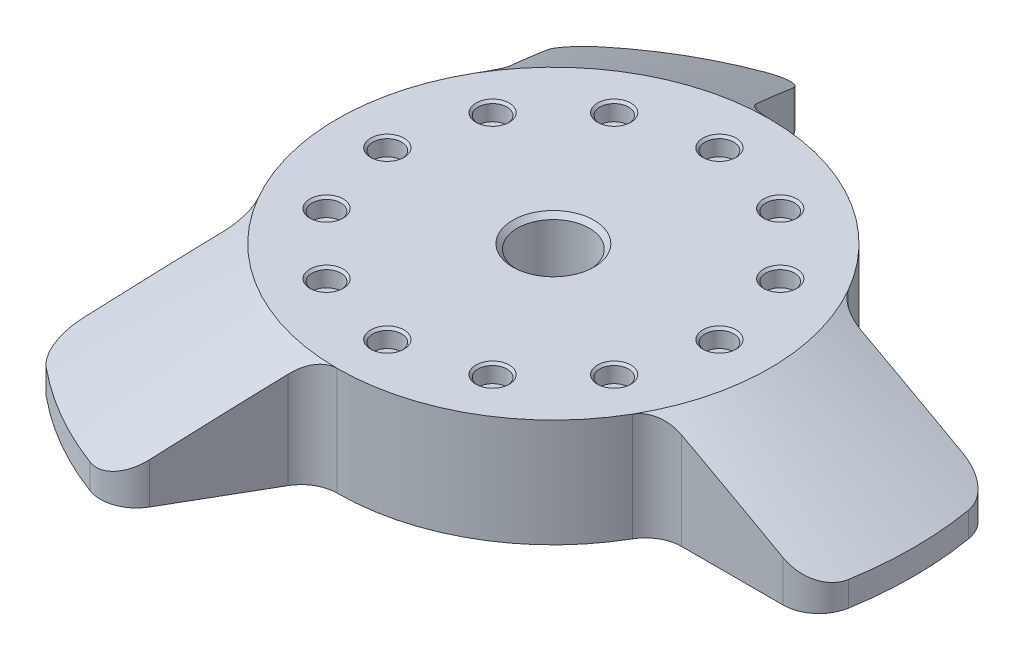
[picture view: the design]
ISO-10303-21;
HEADER;
FILE_DESCRIPTION(('STEP AP214'),'2;1');
FILE_NAME('part.step','',(''),(''),'','','');
FILE_SCHEMA(('AUTOMOTIVE_DESIGN { 1 0 10303 214 1 1 1 1 }'));
ENDSEC;
DATA;
#1=APPLICATION_CONTEXT('core data for automotive mechanical design processes');
#2=APPLICATION_PROTOCOL_DEFINITION('international standard','automotive_design',2000,#1);
#3=PRODUCT_CONTEXT('',#1,'mechanical');
#4=PRODUCT('Part','Part','',(#3));
#5=PRODUCT_RELATED_PRODUCT_CATEGORY('part','',(#4));
#6=PRODUCT_DEFINITION_FORMATION('','',#4);
#7=PRODUCT_DEFINITION_CONTEXT('part definition',#1,'design');
#8=PRODUCT_DEFINITION('design','',#6,#7);
#9=PRODUCT_DEFINITION_SHAPE('','',#8);
#10=(LENGTH_UNIT() NAMED_UNIT(*) SI_UNIT(.MILLI.,.METRE.));
#11=(NAMED_UNIT(*) PLANE_ANGLE_UNIT() SI_UNIT($,.RADIAN.));
#12=(NAMED_UNIT(*) SI_UNIT($,.STERADIAN.) SOLID_ANGLE_UNIT());
#13=UNCERTAINTY_MEASURE_WITH_UNIT(LENGTH_MEASURE(1.E-05),#10,'distance_accuracy_value','');
#14=(GEOMETRIC_REPRESENTATION_CONTEXT(3) GLOBAL_UNCERTAINTY_ASSIGNED_CONTEXT((#13)) GLOBAL_UNIT_ASSIGNED_CONTEXT((#10,
#11,#12)) REPRESENTATION_CONTEXT('',''));
#15=CARTESIAN_POINT('',(0.,0.,0.));
#16=DIRECTION('',(0.,0.,1.));
#17=DIRECTION('',(1.,0.,0.));
#18=AXIS2_PLACEMENT_3D('',#15,#16,#17);
#19=CARTESIAN_POINT('',(0.,19.05,0.));
#20=DIRECTION('',(0.,-1.,0.));
#21=DIRECTION('',(0.,0.,-1.));
#22=AXIS2_PLACEMENT_3D('',#19,#20,#21);
#23=CYLINDRICAL_SURFACE('',#22,38.1);
#24=CARTESIAN_POINT('',(0.,0.,0.));
#25=DIRECTION('',(0.,1.,0.));
#26=DIRECTION('',(0.,0.,1.));
#27=AXIS2_PLACEMENT_3D('',#24,#25,#26);
#28=CIRCLE('',#27,38.1);
#29=CARTESIAN_POINT('',(2.73590673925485E-13,0.,38.1));
#30=VERTEX_POINT('',#29);
#31=CARTESIAN_POINT('',(32.9955678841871,0.,19.05));
#32=VERTEX_POINT('',#31);
#33=EDGE_CURVE('E501',#30,#32,#28,.T.);
#34=ORIENTED_EDGE('',*,*,#33,.T.);
#35=DIRECTION('',(0.,-1.,0.));
#36=VECTOR('',#35,1.);
#37=CARTESIAN_POINT('',(32.9955678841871,19.05,19.05));
#38=LINE('',#37,#36);
#39=CARTESIAN_POINT('',(32.9955678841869,19.05,19.0499999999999));
#40=VERTEX_POINT('',#39);
#41=EDGE_CURVE('E508',#32,#40,#38,.F.);
#42=ORIENTED_EDGE('',*,*,#41,.T.);
#43=CARTESIAN_POINT('',(0.,19.05,0.));
#44=DIRECTION('',(0.,1.,0.));
#45=DIRECTION('',(0.,0.,1.));
#46=AXIS2_PLACEMENT_3D('',#43,#44,#45);
#47=CIRCLE('',#46,38.1);
#48=CARTESIAN_POINT('',(2.73590673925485E-13,19.05,38.1));
#49=VERTEX_POINT('',#48);
#50=EDGE_CURVE('E498',#49,#40,#47,.T.);
#51=ORIENTED_EDGE('',*,*,#50,.F.);
#52=DIRECTION('',(0.,-1.,0.));
#53=VECTOR('',#52,1.);
#54=CARTESIAN_POINT('',(2.73590673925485E-13,19.05,38.1));
#55=LINE('',#54,#53);
#56=EDGE_CURVE('E505',#49,#30,#55,.T.);
#57=ORIENTED_EDGE('',*,*,#56,.T.);
#58=EDGE_LOOP('',(#34,#42,#51,#57));
#59=FACE_BOUND('',#58,.T.);
#60=ADVANCED_FACE('F32',(#59),#23,.T.);
#61=CARTESIAN_POINT('',(-32.9955678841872,0.,-19.0499999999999));
#62=VERTEX_POINT('',#61);
#63=CARTESIAN_POINT('',(-32.995567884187,0.,19.0500000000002));
#64=VERTEX_POINT('',#63);
#65=EDGE_CURVE('E499',#62,#64,#28,.T.);
#66=ORIENTED_EDGE('',*,*,#65,.T.);
#67=DIRECTION('',(0.,-1.,0.));
#68=VECTOR('',#67,1.);
#69=CARTESIAN_POINT('',(-32.995567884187,19.05,19.0500000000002));
#70=LINE('',#69,#68);
#71=CARTESIAN_POINT('',(-32.9955678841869,19.05,19.0500000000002));
#72=VERTEX_POINT('',#71);
#73=EDGE_CURVE('E510',#64,#72,#70,.F.);
#74=ORIENTED_EDGE('',*,*,#73,.T.);
#75=CARTESIAN_POINT('',(-32.9955678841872,19.05,-19.0499999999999));
#76=VERTEX_POINT('',#75);
#77=EDGE_CURVE('E593',#76,#72,#47,.T.);
#78=ORIENTED_EDGE('',*,*,#77,.F.);
#79=DIRECTION('',(0.,-1.,0.));
#80=VECTOR('',#79,1.);
#81=CARTESIAN_POINT('',(-32.9955678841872,19.05,-19.0499999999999));
#82=LINE('',#81,#80);
#83=EDGE_CURVE('E588',#76,#62,#82,.T.);
#84=ORIENTED_EDGE('',*,*,#83,.T.);
#85=EDGE_LOOP('',(#66,#74,#78,#84));
#86=FACE_BOUND('',#85,.T.);
#87=ADVANCED_FACE('F467',(#86),#23,.T.);
#88=CARTESIAN_POINT('',(0.,19.05,0.));
#89=DIRECTION('',(0.,1.,0.));
#90=DIRECTION('',(0.,0.,1.));
#91=AXIS2_PLACEMENT_3D('',#88,#89,#90);
#92=PLANE('',#91);
#93=CARTESIAN_POINT('',(-14.63675,19.05,25.3515946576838));
#94=DIRECTION('',(0.,1.,0.));
#95=DIRECTION('',(0.,0.,1.));
#96=AXIS2_PLACEMENT_3D('',#93,#94,#95);
#97=CIRCLE('',#96,2.9464);
#98=CARTESIAN_POINT('',(-14.63675,19.05,28.2979946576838));
#99=VERTEX_POINT('',#98);
#100=EDGE_CURVE('E418',#99,#99,#97,.F.);
#101=ORIENTED_EDGE('',*,*,#100,.T.);
#102=EDGE_LOOP('',(#101));
#103=FACE_BOUND('',#102,.T.);
#104=CARTESIAN_POINT('',(-3.98986399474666E-13,19.05,29.2735));
#105=DIRECTION('',(0.,1.,0.));
#106=DIRECTION('',(0.,0.,1.));
#107=AXIS2_PLACEMENT_3D('',#104,#105,#106);
#108=CIRCLE('',#107,2.9464);
#109=CARTESIAN_POINT('',(-3.98986399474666E-13,19.05,32.2199));
#110=VERTEX_POINT('',#109);
#111=EDGE_CURVE('E415',#110,#110,#108,.F.);
#112=ORIENTED_EDGE('',*,*,#111,.T.);
#113=EDGE_LOOP('',(#112));
#114=FACE_BOUND('',#113,.T.);
#115=CARTESIAN_POINT('',(14.6367499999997,19.05,25.351594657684));
#116=DIRECTION('',(0.,1.,0.));
#117=DIRECTION('',(0.,0.,1.));
#118=AXIS2_PLACEMENT_3D('',#115,#116,#117);
#119=CIRCLE('',#118,2.94640000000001);
#120=CARTESIAN_POINT('',(14.6367499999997,19.05,28.297994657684));
#121=VERTEX_POINT('',#120);
#122=EDGE_CURVE('E412',#121,#121,#119,.F.);
#123=ORIENTED_EDGE('',*,*,#122,.T.);
#124=EDGE_LOOP('',(#123));
#125=FACE_BOUND('',#124,.T.);
#126=CARTESIAN_POINT('',(25.3515946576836,19.05,14.6367500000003));
#127=DIRECTION('',(0.,1.,0.));
#128=DIRECTION('',(0.,0.,1.));
#129=AXIS2_PLACEMENT_3D('',#126,#127,#128);
#130=CIRCLE('',#129,2.9464);
#131=CARTESIAN_POINT('',(25.3515946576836,19.05,17.5831500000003));
#132=VERTEX_POINT('',#131);
#133=EDGE_CURVE('E409',#132,#132,#130,.F.);
#134=ORIENTED_EDGE('',*,*,#133,.T.);
#135=EDGE_LOOP('',(#134));
#136=FACE_BOUND('',#135,.T.);
#137=CARTESIAN_POINT('',(29.2735,19.05,3.03576608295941E-13));
#138=DIRECTION('',(0.,1.,0.));
#139=DIRECTION('',(0.,0.,1.));
#140=AXIS2_PLACEMENT_3D('',#137,#138,#139);
#141=CIRCLE('',#140,2.9464);
#142=CARTESIAN_POINT('',(29.2735,19.05,2.94640000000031));
#143=VERTEX_POINT('',#142);
#144=EDGE_CURVE('E406',#143,#143,#141,.F.);
#145=ORIENTED_EDGE('',*,*,#144,.T.);
#146=EDGE_LOOP('',(#145));
#147=FACE_BOUND('',#146,.T.);
#148=CARTESIAN_POINT('',(25.3515946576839,19.05,-14.6367499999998));
#149=DIRECTION('',(0.,1.,0.));
#150=DIRECTION('',(0.,0.,1.));
#151=AXIS2_PLACEMENT_3D('',#148,#149,#150);
#152=CIRCLE('',#151,2.9464);
#153=CARTESIAN_POINT('',(25.3515946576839,19.05,-11.6903499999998));
#154=VERTEX_POINT('',#153);
#155=EDGE_CURVE('E403',#154,#154,#152,.F.);
#156=ORIENTED_EDGE('',*,*,#155,.T.);
#157=EDGE_LOOP('',(#156));
#158=FACE_BOUND('',#157,.T.);
#159=CARTESIAN_POINT('',(14.6367500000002,19.05,-25.3515946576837));
#160=DIRECTION('',(0.,1.,0.));
#161=DIRECTION('',(0.,0.,1.));
#162=AXIS2_PLACEMENT_3D('',#159,#160,#161);
#163=CIRCLE('',#162,2.9464);
#164=CARTESIAN_POINT('',(14.6367500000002,19.05,-22.4051946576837));
#165=VERTEX_POINT('',#164);
#166=EDGE_CURVE('E400',#165,#165,#163,.F.);
#167=ORIENTED_EDGE('',*,*,#166,.T.);
#168=EDGE_LOOP('',(#167));
#169=FACE_BOUND('',#168,.T.);
#170=CARTESIAN_POINT('',(1.96023752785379E-13,19.05,-29.2735));
#171=DIRECTION('',(0.,1.,0.));
#172=DIRECTION('',(0.,0.,1.));
#173=AXIS2_PLACEMENT_3D('',#170,#171,#172);
#174=CIRCLE('',#173,2.9464);
#175=CARTESIAN_POINT('',(1.96023752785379E-13,19.05,-26.3271));
#176=VERTEX_POINT('',#175);
#177=EDGE_CURVE('E397',#176,#176,#174,.F.);
#178=ORIENTED_EDGE('',*,*,#177,.T.);
#179=EDGE_LOOP('',(#178));
#180=FACE_BOUND('',#179,.T.);
#181=CARTESIAN_POINT('',(-14.6367499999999,19.05,-25.3515946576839));
#182=DIRECTION('',(0.,1.,0.));
#183=DIRECTION('',(0.,0.,1.));
#184=AXIS2_PLACEMENT_3D('',#181,#182,#183);
#185=CIRCLE('',#184,2.9464);
#186=CARTESIAN_POINT('',(-14.6367499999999,19.05,-22.4051946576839));
#187=VERTEX_POINT('',#186);
#188=EDGE_CURVE('E394',#187,#187,#185,.F.);
#189=ORIENTED_EDGE('',*,*,#188,.T.);
#190=EDGE_LOOP('',(#189));
#191=FACE_BOUND('',#190,.T.);
#192=CARTESIAN_POINT('',(-25.3515946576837,19.05,-14.6367500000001));
#193=DIRECTION('',(0.,1.,0.));
#194=DIRECTION('',(0.,0.,1.));
#195=AXIS2_PLACEMENT_3D('',#192,#193,#194);
#196=CIRCLE('',#195,2.9464);
#197=CARTESIAN_POINT('',(-25.3515946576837,19.05,-11.6903500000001));
#198=VERTEX_POINT('',#197);
#199=EDGE_CURVE('E391',#198,#198,#196,.F.);
#200=ORIENTED_EDGE('',*,*,#199,.T.);
#201=EDGE_LOOP('',(#200));
#202=FACE_BOUND('',#201,.T.);
#203=CARTESIAN_POINT('',(-29.2735,19.05,0.));
#204=DIRECTION('',(0.,1.,0.));
#205=DIRECTION('',(0.,0.,1.));
#206=AXIS2_PLACEMENT_3D('',#203,#204,#205);
#207=CIRCLE('',#206,2.9464);
#208=CARTESIAN_POINT('',(-29.2735,19.05,2.9463999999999));
#209=VERTEX_POINT('',#208);
#210=EDGE_CURVE('E388',#209,#209,#207,.F.);
#211=ORIENTED_EDGE('',*,*,#210,.T.);
#212=EDGE_LOOP('',(#211));
#213=FACE_BOUND('',#212,.T.);
#214=CARTESIAN_POINT('',(-25.3515946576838,19.05,14.63675));
#215=DIRECTION('',(0.,1.,0.));
#216=DIRECTION('',(0.,0.,1.));
#217=AXIS2_PLACEMENT_3D('',#214,#215,#216);
#218=CIRCLE('',#217,2.9464);
#219=CARTESIAN_POINT('',(-25.3515946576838,19.05,17.58315));
#220=VERTEX_POINT('',#219);
#221=EDGE_CURVE('E385',#220,#220,#218,.F.);
#222=ORIENTED_EDGE('',*,*,#221,.T.);
#223=EDGE_LOOP('',(#222));
#224=FACE_BOUND('',#223,.T.);
#225=CARTESIAN_POINT('',(0.,19.05,0.));
#226=DIRECTION('',(0.,1.,0.));
#227=DIRECTION('',(0.,0.,1.));
#228=AXIS2_PLACEMENT_3D('',#225,#226,#227);
#229=CIRCLE('',#228,7.16280000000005);
#230=CARTESIAN_POINT('',(0.,19.05,7.16280000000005));
#231=VERTEX_POINT('',#230);
#232=EDGE_CURVE('E379',#231,#231,#229,.F.);
#233=ORIENTED_EDGE('',*,*,#232,.T.);
#234=EDGE_LOOP('',(#233));
#235=FACE_BOUND('',#234,.T.);
#236=CARTESIAN_POINT('',(0.,19.05,0.));
#237=DIRECTION('',(0.,1.,0.));
#238=DIRECTION('',(0.,0.,1.));
#239=AXIS2_PLACEMENT_3D('',#236,#237,#238);
#240=CIRCLE('',#239,38.0999999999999);
#241=EDGE_CURVE('E47',#72,#49,#240,.T.);
#242=ORIENTED_EDGE('',*,*,#241,.T.);
#243=ORIENTED_EDGE('',*,*,#50,.T.);
#244=CARTESIAN_POINT('',(0.,19.05,0.));
#245=DIRECTION('',(0.,1.,0.));
#246=DIRECTION('',(0.,0.,1.));
#247=AXIS2_PLACEMENT_3D('',#244,#245,#246);
#248=CIRCLE('',#247,38.0999999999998);
#249=CARTESIAN_POINT('',(32.9955678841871,19.05,-19.05));
#250=VERTEX_POINT('',#249);
#251=EDGE_CURVE('E54',#40,#250,#248,.T.);
#252=ORIENTED_EDGE('',*,*,#251,.T.);
#253=CARTESIAN_POINT('',(-1.30847713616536E-13,19.05,-38.0999999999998));
#254=VERTEX_POINT('',#253);
#255=EDGE_CURVE('E225',#250,#254,#47,.T.);
#256=ORIENTED_EDGE('',*,*,#255,.T.);
#257=CARTESIAN_POINT('',(0.,19.05,0.));
#258=DIRECTION('',(0.,1.,0.));
#259=DIRECTION('',(0.,0.,1.));
#260=AXIS2_PLACEMENT_3D('',#257,#258,#259);
#261=CIRCLE('',#260,38.0999999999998);
#262=EDGE_CURVE('E70',#254,#76,#261,.T.);
#263=ORIENTED_EDGE('',*,*,#262,.T.);
#264=ORIENTED_EDGE('',*,*,#77,.T.);
#265=EDGE_LOOP('',(#242,#243,#252,#256,#263,#264));
#266=FACE_BOUND('',#265,.T.);
#267=ADVANCED_FACE('F473',(#103,#114,#125,#136,#147,#158,#169,#180,#191,#202,#213,#224,#235,
#266),#92,.T.);
#268=CARTESIAN_POINT('',(0.,0.,0.));
#269=DIRECTION('',(0.,1.,0.));
#270=DIRECTION('',(0.,0.,1.));
#271=AXIS2_PLACEMENT_3D('',#268,#269,#270);
#272=PLANE('',#271);
#273=CARTESIAN_POINT('',(0.,0.,0.));
#274=DIRECTION('',(0.,1.,0.));
#275=DIRECTION('',(0.,0.,1.));
#276=AXIS2_PLACEMENT_3D('',#273,#274,#275);
#277=CIRCLE('',#276,7.16279999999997);
#278=CARTESIAN_POINT('',(0.,0.,-7.16279999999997));
#279=VERTEX_POINT('',#278);
#280=EDGE_CURVE('E370',#279,#279,#277,.T.);
#281=ORIENTED_EDGE('',*,*,#280,.T.);
#282=EDGE_LOOP('',(#281));
#283=FACE_BOUND('',#282,.T.);
#284=CARTESIAN_POINT('',(0.,0.,0.));
#285=DIRECTION('',(0.,-1.,0.));
#286=DIRECTION('',(0.,0.,-1.));
#287=AXIS2_PLACEMENT_3D('',#284,#285,#286);
#288=CIRCLE('',#287,63.5);
#289=CARTESIAN_POINT('',(62.6118443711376,0.,-10.5833333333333));
#290=VERTEX_POINT('',#289);
#291=CARTESIAN_POINT('',(62.6118443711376,0.,10.5833333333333));
#292=VERTEX_POINT('',#291);
#293=EDGE_CURVE('E211',#290,#292,#288,.T.);
#294=ORIENTED_EDGE('',*,*,#293,.T.);
#295=CARTESIAN_POINT('',(56.3506599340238,0.,9.525));
#296=DIRECTION('',(0.,1.,0.));
#297=DIRECTION('',(0.,0.,1.));
#298=AXIS2_PLACEMENT_3D('',#295,#296,#297);
#299=CIRCLE('',#298,6.35);
#300=CARTESIAN_POINT('',(56.3506599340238,0.,15.875));
#301=VERTEX_POINT('',#300);
#302=EDGE_CURVE('E1368',#292,#301,#299,.F.);
#303=ORIENTED_EDGE('',*,*,#302,.T.);
#304=DIRECTION('',(-1.,0.,0.));
#305=VECTOR('',#304,1.);
#306=CARTESIAN_POINT('',(34.6351609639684,0.,15.875));
#307=LINE('',#306,#305);
#308=CARTESIAN_POINT('',(38.4948291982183,0.,15.875));
#309=VERTEX_POINT('',#308);
#310=EDGE_CURVE('E620',#301,#309,#307,.T.);
#311=ORIENTED_EDGE('',*,*,#310,.T.);
#312=CARTESIAN_POINT('',(38.4948291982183,0.,22.225));
#313=DIRECTION('',(0.,1.,0.));
#314=DIRECTION('',(0.,0.,1.));
#315=AXIS2_PLACEMENT_3D('',#312,#313,#314);
#316=CIRCLE('',#315,6.35);
#317=EDGE_CURVE('E344',#309,#32,#316,.T.);
#318=ORIENTED_EDGE('',*,*,#317,.T.);
#319=ORIENTED_EDGE('',*,*,#33,.F.);
#320=CARTESIAN_POINT('',(3.19189119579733E-13,0.,44.45));
#321=DIRECTION('',(0.,1.,0.));
#322=DIRECTION('',(0.,0.,1.));
#323=AXIS2_PLACEMENT_3D('',#320,#321,#322);
#324=CIRCLE('',#323,6.35);
#325=CARTESIAN_POINT('',(-5.49926131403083,0.,41.2749999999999));
#326=VERTEX_POINT('',#325);
#327=EDGE_CURVE('E351',#30,#326,#324,.T.);
#328=ORIENTED_EDGE('',*,*,#327,.T.);
#329=DIRECTION('',(-0.50000000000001,0.,0.866025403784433));
#330=VECTOR('',#329,1.);
#331=CARTESIAN_POINT('',(-3.56942719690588,0.,37.9324292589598));
#332=LINE('',#331,#330);
#333=CARTESIAN_POINT('',(-14.4271766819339,0.,56.7386030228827));
#334=VERTEX_POINT('',#333);
#335=EDGE_CURVE('E606',#326,#334,#332,.T.);
#336=ORIENTED_EDGE('',*,*,#335,.T.);
#337=CARTESIAN_POINT('',(-19.9264379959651,0.,53.5636030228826));
#338=DIRECTION('',(0.,1.,0.));
#339=DIRECTION('',(0.,0.,1.));
#340=AXIS2_PLACEMENT_3D('',#337,#338,#339);
#341=CIRCLE('',#340,6.35);
#342=CARTESIAN_POINT('',(-22.1404866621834,0.,59.5151144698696));
#343=VERTEX_POINT('',#342);
#344=EDGE_CURVE('E1363',#334,#343,#341,.F.);
#345=ORIENTED_EDGE('',*,*,#344,.T.);
#346=CARTESIAN_POINT('',(0.,0.,0.));
#347=DIRECTION('',(0.,-1.,0.));
#348=DIRECTION('',(0.,0.,-1.));
#349=AXIS2_PLACEMENT_3D('',#346,#347,#348);
#350=CIRCLE('',#349,63.5);
#351=CARTESIAN_POINT('',(-40.4713577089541,0.,48.9317811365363));
#352=VERTEX_POINT('',#351);
#353=EDGE_CURVE('E604',#343,#352,#350,.T.);
#354=ORIENTED_EDGE('',*,*,#353,.T.);
#355=CARTESIAN_POINT('',(-36.4242219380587,0.,44.0386030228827));
#356=DIRECTION('',(0.,1.,0.));
#357=DIRECTION('',(0.,0.,1.));
#358=AXIS2_PLACEMENT_3D('',#355,#356,#357);
#359=CIRCLE('',#358,6.35);
#360=CARTESIAN_POINT('',(-41.9234832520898,0.,40.8636030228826));
#361=VERTEX_POINT('',#360);
#362=EDGE_CURVE('E603',#352,#361,#359,.F.);
#363=ORIENTED_EDGE('',*,*,#362,.T.);
#364=DIRECTION('',(0.50000000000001,0.,-0.866025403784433));
#365=VECTOR('',#364,1.);
#366=CARTESIAN_POINT('',(-31.065733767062,0.,22.05742925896));
#367=LINE('',#366,#365);
#368=CARTESIAN_POINT('',(-32.995567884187,0.,25.4000000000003));
#369=VERTEX_POINT('',#368);
#370=EDGE_CURVE('E539',#361,#369,#367,.T.);
#371=ORIENTED_EDGE('',*,*,#370,.T.);
#372=CARTESIAN_POINT('',(-38.4948291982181,0.,22.2250000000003));
#373=DIRECTION('',(0.,1.,0.));
#374=DIRECTION('',(0.,0.,1.));
#375=AXIS2_PLACEMENT_3D('',#372,#373,#374);
#376=CIRCLE('',#375,6.35);
#377=EDGE_CURVE('E515',#369,#64,#376,.T.);
#378=ORIENTED_EDGE('',*,*,#377,.T.);
#379=ORIENTED_EDGE('',*,*,#65,.F.);
#380=CARTESIAN_POINT('',(-38.4948291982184,0.,-22.2249999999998));
#381=DIRECTION('',(0.,1.,0.));
#382=DIRECTION('',(0.,0.,1.));
#383=AXIS2_PLACEMENT_3D('',#380,#381,#382);
#384=CIRCLE('',#383,6.35);
#385=CARTESIAN_POINT('',(-32.9955678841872,0.,-25.3999999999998));
#386=VERTEX_POINT('',#385);
#387=EDGE_CURVE('E313',#62,#386,#384,.T.);
#388=ORIENTED_EDGE('',*,*,#387,.T.);
#389=DIRECTION('',(-0.499999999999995,0.,-0.866025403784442));
#390=VECTOR('',#389,1.);
#391=CARTESIAN_POINT('',(-31.0657337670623,0.,-22.0574292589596));
#392=LINE('',#391,#390);
#393=CARTESIAN_POINT('',(-41.9234832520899,0.,-40.8636030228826));
#394=VERTEX_POINT('',#393);
#395=EDGE_CURVE('E526',#386,#394,#392,.T.);
#396=ORIENTED_EDGE('',*,*,#395,.T.);
#397=CARTESIAN_POINT('',(-36.4242219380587,0.,-44.0386030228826));
#398=DIRECTION('',(0.,1.,0.));
#399=DIRECTION('',(0.,0.,1.));
#400=AXIS2_PLACEMENT_3D('',#397,#398,#399);
#401=CIRCLE('',#400,6.35);
#402=CARTESIAN_POINT('',(-40.4713577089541,0.,-48.9317811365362));
#403=VERTEX_POINT('',#402);
#404=EDGE_CURVE('E1357',#394,#403,#401,.F.);
#405=ORIENTED_EDGE('',*,*,#404,.T.);
#406=CARTESIAN_POINT('',(0.,0.,0.));
#407=DIRECTION('',(0.,-1.,0.));
#408=DIRECTION('',(0.,0.,-1.));
#409=AXIS2_PLACEMENT_3D('',#406,#407,#408);
#410=CIRCLE('',#409,63.5);
#411=CARTESIAN_POINT('',(-22.1404866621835,0.,-59.5151144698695));
#412=VERTEX_POINT('',#411);
#413=EDGE_CURVE('E538',#403,#412,#410,.T.);
#414=ORIENTED_EDGE('',*,*,#413,.T.);
#415=CARTESIAN_POINT('',(-19.9264379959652,0.,-53.5636030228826));
#416=DIRECTION('',(0.,1.,0.));
#417=DIRECTION('',(0.,0.,1.));
#418=AXIS2_PLACEMENT_3D('',#415,#416,#417);
#419=CIRCLE('',#418,6.35);
#420=CARTESIAN_POINT('',(-14.427176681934,0.,-56.7386030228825));
#421=VERTEX_POINT('',#420);
#422=EDGE_CURVE('E1359',#412,#421,#419,.F.);
#423=ORIENTED_EDGE('',*,*,#422,.T.);
#424=DIRECTION('',(0.499999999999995,0.,0.866025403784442));
#425=VECTOR('',#424,1.);
#426=CARTESIAN_POINT('',(-3.56942719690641,0.,-37.9324292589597));
#427=LINE('',#426,#425);
#428=CARTESIAN_POINT('',(-5.49926131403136,0.,-41.275));
#429=VERTEX_POINT('',#428);
#430=EDGE_CURVE('E614',#421,#429,#427,.T.);
#431=ORIENTED_EDGE('',*,*,#430,.T.);
#432=CARTESIAN_POINT('',(-1.52655665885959E-13,0.,-44.45));
#433=DIRECTION('',(0.,1.,0.));
#434=DIRECTION('',(0.,0.,1.));
#435=AXIS2_PLACEMENT_3D('',#432,#433,#434);
#436=CIRCLE('',#435,6.35);
#437=CARTESIAN_POINT('',(-1.30847713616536E-13,0.,-38.1));
#438=VERTEX_POINT('',#437);
#439=EDGE_CURVE('E312',#429,#438,#436,.T.);
#440=ORIENTED_EDGE('',*,*,#439,.T.);
#441=CARTESIAN_POINT('',(32.9955678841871,0.,-19.05));
#442=VERTEX_POINT('',#441);
#443=EDGE_CURVE('E492',#442,#438,#28,.T.);
#444=ORIENTED_EDGE('',*,*,#443,.F.);
#445=CARTESIAN_POINT('',(38.4948291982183,0.,-22.225));
#446=DIRECTION('',(0.,1.,0.));
#447=DIRECTION('',(0.,0.,1.));
#448=AXIS2_PLACEMENT_3D('',#445,#446,#447);
#449=CIRCLE('',#448,6.35);
#450=CARTESIAN_POINT('',(38.4948291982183,0.,-15.875));
#451=VERTEX_POINT('',#450);
#452=EDGE_CURVE('E337',#442,#451,#449,.T.);
#453=ORIENTED_EDGE('',*,*,#452,.T.);
#454=DIRECTION('',(1.,0.,0.));
#455=VECTOR('',#454,1.);
#456=CARTESIAN_POINT('',(34.6351609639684,0.,-15.875));
#457=LINE('',#456,#455);
#458=CARTESIAN_POINT('',(56.3506599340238,0.,-15.875));
#459=VERTEX_POINT('',#458);
#460=EDGE_CURVE('E617',#451,#459,#457,.T.);
#461=ORIENTED_EDGE('',*,*,#460,.T.);
#462=CARTESIAN_POINT('',(56.3506599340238,0.,-9.525));
#463=DIRECTION('',(0.,1.,0.));
#464=DIRECTION('',(0.,0.,1.));
#465=AXIS2_PLACEMENT_3D('',#462,#463,#464);
#466=CIRCLE('',#465,6.35);
#467=EDGE_CURVE('E1361',#459,#290,#466,.F.);
#468=ORIENTED_EDGE('',*,*,#467,.T.);
#469=EDGE_LOOP('',(#294,#303,#311,#318,#319,#328,#336,#345,#354,#363,#371,#378,#379,#388,#396,
#405,#414,#423,#431,#440,#444,#453,#461,#468));
#470=FACE_BOUND('',#469,.T.);
#471=ADVANCED_FACE('F479',(#283,#470),#272,.F.);
#472=ORIENTED_EDGE('',*,*,#443,.T.);
#473=DIRECTION('',(0.,-1.,0.));
#474=VECTOR('',#473,1.);
#475=CARTESIAN_POINT('',(-1.30847713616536E-13,19.05,-38.1));
#476=LINE('',#475,#474);
#477=EDGE_CURVE('E494',#438,#254,#476,.F.);
#478=ORIENTED_EDGE('',*,*,#477,.T.);
#479=ORIENTED_EDGE('',*,*,#255,.F.);
#480=DIRECTION('',(0.,-1.,0.));
#481=VECTOR('',#480,1.);
#482=CARTESIAN_POINT('',(32.9955678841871,19.05,-19.05));
#483=LINE('',#482,#481);
#484=EDGE_CURVE('E496',#250,#442,#483,.T.);
#485=ORIENTED_EDGE('',*,*,#484,.T.);
#486=EDGE_LOOP('',(#472,#478,#479,#485));
#487=FACE_BOUND('',#486,.T.);
#488=ADVANCED_FACE('F469',(#487),#23,.T.);
#489=CARTESIAN_POINT('',(0.,19.05,0.));
#490=DIRECTION('',(0.,-1.,0.));
#491=DIRECTION('',(0.,0.,-1.));
#492=AXIS2_PLACEMENT_3D('',#489,#490,#491);
#493=CYLINDRICAL_SURFACE('',#492,6.35);
#494=CARTESIAN_POINT('',(0.,0.812799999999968,0.));
#495=DIRECTION('',(0.,1.,0.));
#496=DIRECTION('',(0.,0.,1.));
#497=AXIS2_PLACEMENT_3D('',#494,#495,#496);
#498=CIRCLE('',#497,6.35);
#499=CARTESIAN_POINT('',(0.,0.812799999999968,-6.35));
#500=VERTEX_POINT('',#499);
#501=EDGE_CURVE('E376',#500,#500,#498,.F.);
#502=CARTESIAN_POINT('',(0.,18.2371999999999,0.));
#503=DIRECTION('',(0.,1.,0.));
#504=DIRECTION('',(0.,0.,1.));
#505=AXIS2_PLACEMENT_3D('',#502,#503,#504);
#506=CIRCLE('',#505,6.35);
#507=CARTESIAN_POINT('',(0.,18.2371999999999,-6.35));
#508=VERTEX_POINT('',#507);
#509=EDGE_CURVE('E373',#508,#508,#506,.T.);
#510=CARTESIAN_POINT('',(0.,0.812799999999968,-6.35));
#511=CARTESIAN_POINT('',(0.,0.994304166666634,-6.35));
#512=CARTESIAN_POINT('',(0.,1.1758083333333,-6.35));
#513=CARTESIAN_POINT('',(0.,1.53881666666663,-6.35));
#514=CARTESIAN_POINT('',(0.,1.7203208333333,-6.35));
#515=CARTESIAN_POINT('',(0.,2.08332916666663,-6.35));
#516=CARTESIAN_POINT('',(0.,2.2648333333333,-6.35));
#517=CARTESIAN_POINT('',(0.,2.62784166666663,-6.35));
#518=CARTESIAN_POINT('',(0.,2.8093458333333,-6.35));
#519=CARTESIAN_POINT('',(0.,3.17235416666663,-6.35));
#520=CARTESIAN_POINT('',(0.,3.3538583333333,-6.35));
#521=CARTESIAN_POINT('',(0.,3.71686666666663,-6.35));
#522=CARTESIAN_POINT('',(0.,3.8983708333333,-6.35));
#523=CARTESIAN_POINT('',(0.,4.26137916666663,-6.35));
#524=CARTESIAN_POINT('',(0.,4.44288333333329,-6.35));
#525=CARTESIAN_POINT('',(0.,4.80589166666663,-6.35));
#526=CARTESIAN_POINT('',(0.,4.98739583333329,-6.35));
#527=CARTESIAN_POINT('',(0.,5.35040416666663,-6.35));
#528=CARTESIAN_POINT('',(0.,5.53190833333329,-6.35));
#529=CARTESIAN_POINT('',(0.,5.89491666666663,-6.35));
#530=CARTESIAN_POINT('',(0.,6.07642083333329,-6.35));
#531=CARTESIAN_POINT('',(0.,6.43942916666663,-6.35));
#532=CARTESIAN_POINT('',(0.,6.62093333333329,-6.35));
#533=CARTESIAN_POINT('',(0.,6.98394166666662,-6.35));
#534=CARTESIAN_POINT('',(0.,7.16544583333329,-6.35));
#535=CARTESIAN_POINT('',(0.,7.52845416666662,-6.35));
#536=CARTESIAN_POINT('',(0.,7.70995833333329,-6.35));
#537=CARTESIAN_POINT('',(0.,8.07296666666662,-6.35));
#538=CARTESIAN_POINT('',(0.,8.25447083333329,-6.35));
#539=CARTESIAN_POINT('',(0.,8.61747916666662,-6.35));
#540=CARTESIAN_POINT('',(0.,8.79898333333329,-6.35));
#541=CARTESIAN_POINT('',(0.,9.16199166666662,-6.35));
#542=CARTESIAN_POINT('',(0.,9.34349583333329,-6.35));
#543=CARTESIAN_POINT('',(0.,9.70650416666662,-6.35));
#544=CARTESIAN_POINT('',(0.,9.88800833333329,-6.35));
#545=CARTESIAN_POINT('',(0.,10.2510166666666,-6.35));
#546=CARTESIAN_POINT('',(0.,10.4325208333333,-6.35));
#547=CARTESIAN_POINT('',(0.,10.7955291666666,-6.35));
#548=CARTESIAN_POINT('',(0.,10.9770333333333,-6.35));
#549=CARTESIAN_POINT('',(0.,11.3400416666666,-6.35));
#550=CARTESIAN_POINT('',(0.,11.5215458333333,-6.35));
#551=CARTESIAN_POINT('',(0.,11.8845541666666,-6.35));
#552=CARTESIAN_POINT('',(0.,12.0660583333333,-6.35));
#553=CARTESIAN_POINT('',(0.,12.4290666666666,-6.35));
#554=CARTESIAN_POINT('',(0.,12.6105708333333,-6.35));
#555=CARTESIAN_POINT('',(0.,12.9735791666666,-6.35));
#556=CARTESIAN_POINT('',(0.,13.1550833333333,-6.35));
#557=CARTESIAN_POINT('',(0.,13.5180916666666,-6.35));
#558=CARTESIAN_POINT('',(0.,13.6995958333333,-6.35));
#559=CARTESIAN_POINT('',(0.,14.0626041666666,-6.35));
#560=CARTESIAN_POINT('',(0.,14.2441083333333,-6.35));
#561=CARTESIAN_POINT('',(0.,14.6071166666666,-6.35));
#562=CARTESIAN_POINT('',(0.,14.7886208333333,-6.35));
#563=CARTESIAN_POINT('',(0.,15.1516291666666,-6.35));
#564=CARTESIAN_POINT('',(0.,15.3331333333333,-6.35));
#565=CARTESIAN_POINT('',(0.,15.6961416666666,-6.35));
#566=CARTESIAN_POINT('',(0.,15.8776458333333,-6.35));
#567=CARTESIAN_POINT('',(0.,16.2406541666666,-6.35));
#568=CARTESIAN_POINT('',(0.,16.4221583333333,-6.35));
#569=CARTESIAN_POINT('',(0.,16.7851666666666,-6.35));
#570=CARTESIAN_POINT('',(0.,16.9666708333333,-6.35));
#571=CARTESIAN_POINT('',(0.,17.3296791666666,-6.35));
#572=CARTESIAN_POINT('',(0.,17.5111833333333,-6.35));
#573=CARTESIAN_POINT('',(0.,17.8741916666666,-6.35));
#574=CARTESIAN_POINT('',(0.,18.0556958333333,-6.35));
#575=CARTESIAN_POINT('',(0.,18.2371999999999,-6.35));
#576=B_SPLINE_CURVE_WITH_KNOTS('',3,(#510,#511,#512,#513,#514,#515,#516,#517,#518,#519,#520,
#521,#522,#523,#524,#525,#526,#527,#528,#529,#530,#531,#532,#533,#534,#535,#536,#537,#538,#539,
#540,#541,#542,#543,#544,#545,#546,#547,#548,#549,#550,#551,#552,#553,#554,#555,#556,#557,#558,
#559,#560,#561,#562,#563,#564,#565,#566,#567,#568,#569,#570,#571,#572,#573,#574,#575),
.UNSPECIFIED.,.F.,.F.,(4,2,2,2,2,2,2,2,2,2,2,2,2,2,2,2,2,2,2,2,2,2,2,2,2,2,2,2,2,2,2,2,4),(0.,
0.5445125,1.089025,1.6335375,2.17805,2.7225625,3.26707499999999,3.81158749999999,
4.35609999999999,4.90061249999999,5.44512499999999,5.98963749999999,6.53414999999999,
7.07866249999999,7.62317499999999,8.16768749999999,8.71219999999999,9.25671249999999,
9.80122499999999,10.3457375,10.89025,11.4347625,11.979275,12.5237875,13.0683,13.6128125,
14.157325,14.7018375,15.24635,15.7908625,16.335375,16.8798875,17.4244),.UNSPECIFIED.);
#577=EDGE_CURVE('BSEAM478',#500,#508,#576,.T.);
#578=ORIENTED_EDGE('',*,*,#501,.T.);
#579=ORIENTED_EDGE('',*,*,#509,.T.);
#580=ORIENTED_EDGE('',*,*,#577,.T.);
#581=ORIENTED_EDGE('',*,*,#577,.F.);
#582=EDGE_LOOP('',(#578,#580,#579,#581));
#583=FACE_BOUND('',#582,.T.);
#584=ADVANCED_FACE('F478',(#583),#493,.F.);
#585=CARTESIAN_POINT('',(34.6351609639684,75.6659708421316,-15.875));
#586=DIRECTION('',(0.,0.,-1.));
#587=DIRECTION('',(-1.,0.,0.));
#588=AXIS2_PLACEMENT_3D('',#585,#586,#587);
#589=PLANE('',#588);
#590=CARTESIAN_POINT('',(34.6351609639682,19.05,-15.875));
#591=CARTESIAN_POINT('',(35.1995346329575,18.7537846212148,-15.875));
#592=CARTESIAN_POINT('',(35.7633956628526,18.4565946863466,-15.875));
#593=CARTESIAN_POINT('',(36.8901958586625,17.8604751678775,-15.875));
#594=CARTESIAN_POINT('',(37.4531350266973,17.5615455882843,-15.875));
#595=CARTESIAN_POINT('',(39.1407169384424,16.662465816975,-15.875));
#596=CARTESIAN_POINT('',(40.2641359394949,16.0600183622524,-15.875));
#597=CARTESIAN_POINT('',(42.5083076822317,14.850285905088,-15.875));
#598=CARTESIAN_POINT('',(43.6290605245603,14.2430010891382,-15.875));
#599=CARTESIAN_POINT('',(45.8684321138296,13.0245031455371,-15.875));
#600=CARTESIAN_POINT('',(46.9870508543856,12.4132900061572,-15.875));
#601=CARTESIAN_POINT('',(49.2224942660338,11.1876696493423,-15.875));
#602=CARTESIAN_POINT('',(50.3393189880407,10.5732625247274,-15.875));
#603=CARTESIAN_POINT('',(52.5715005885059,9.34178734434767,-15.875));
#604=CARTESIAN_POINT('',(53.6868574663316,8.72471928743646,-15.875));
#605=CARTESIAN_POINT('',(55.916380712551,7.48833622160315,-15.875));
#606=CARTESIAN_POINT('',(57.0305470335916,6.86902112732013,-15.875));
#607=CARTESIAN_POINT('',(59.2578248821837,5.62849872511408,-15.875));
#608=CARTESIAN_POINT('',(60.370936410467,5.00729141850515,-15.875));
#609=CARTESIAN_POINT('',(61.4836106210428,4.38530316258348,-15.875));
#610=B_SPLINE_CURVE_WITH_KNOTS('',3,(#590,#591,#592,#593,#594,#595,#596,#597,#598,#599,#600,
#601,#602,#603,#604,#605,#606,#607,#608,#609),.UNSPECIFIED.,.F.,.F.,(4,2,2,2,2,2,2,2,2,4),(0.,
1.91215613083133,3.82430785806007,7.64857114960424,11.4726877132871,15.2968156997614,
19.12083316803,22.9448522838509,26.7690182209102,30.5931815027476),.UNSPECIFIED.);
#611=CARTESIAN_POINT('',(38.4948291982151,17.0063332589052,-15.875));
#612=VERTEX_POINT('',#611);
#613=CARTESIAN_POINT('',(56.3506599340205,7.24658914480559,-15.875));
#614=VERTEX_POINT('',#613);
#615=EDGE_CURVE('E647',#612,#614,#610,.T.);
#616=ORIENTED_EDGE('',*,*,#615,.T.);
#617=DIRECTION('',(0.,-1.,0.));
#618=VECTOR('',#617,1.);
#619=CARTESIAN_POINT('',(56.3506599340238,75.6659708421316,-15.875));
#620=LINE('',#619,#618);
#621=EDGE_CURVE('E230',#614,#459,#620,.T.);
#622=ORIENTED_EDGE('',*,*,#621,.T.);
#623=ORIENTED_EDGE('',*,*,#460,.F.);
#624=DIRECTION('',(0.,-1.,0.));
#625=VECTOR('',#624,1.);
#626=CARTESIAN_POINT('',(38.4948291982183,75.6659708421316,-15.875));
#627=LINE('',#626,#625);
#628=EDGE_CURVE('E233',#451,#612,#627,.F.);
#629=ORIENTED_EDGE('',*,*,#628,.T.);
#630=EDGE_LOOP('',(#616,#622,#623,#629));
#631=FACE_BOUND('',#630,.T.);
#632=ADVANCED_FACE('F485',(#631),#589,.T.);
#633=CARTESIAN_POINT('',(0.,75.6659708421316,0.));
#634=DIRECTION('',(0.,-1.,0.));
#635=DIRECTION('',(0.,0.,-1.));
#636=AXIS2_PLACEMENT_3D('',#633,#634,#635);
#637=CYLINDRICAL_SURFACE('',#636,63.5);
#638=CARTESIAN_POINT('',(0.,4.38530316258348,0.));
#639=DIRECTION('',(0.,1.,0.));
#640=DIRECTION('',(0.,0.,1.));
#641=AXIS2_PLACEMENT_3D('',#638,#639,#640);
#642=CIRCLE('',#641,63.5);
#643=CARTESIAN_POINT('',(62.6118443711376,4.38530316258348,-10.5833333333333));
#644=VERTEX_POINT('',#643);
#645=CARTESIAN_POINT('',(62.6118443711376,4.38530316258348,10.5833333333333));
#646=VERTEX_POINT('',#645);
#647=EDGE_CURVE('E208',#644,#646,#642,.F.);
#648=ORIENTED_EDGE('',*,*,#647,.T.);
#649=DIRECTION('',(0.,-1.,0.));
#650=VECTOR('',#649,1.);
#651=CARTESIAN_POINT('',(62.6118443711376,75.6659708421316,10.5833333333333));
#652=LINE('',#651,#650);
#653=EDGE_CURVE('E214',#646,#292,#652,.T.);
#654=ORIENTED_EDGE('',*,*,#653,.T.);
#655=ORIENTED_EDGE('',*,*,#293,.F.);
#656=DIRECTION('',(0.,-1.,0.));
#657=VECTOR('',#656,1.);
#658=CARTESIAN_POINT('',(62.6118443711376,75.6659708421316,-10.5833333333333));
#659=LINE('',#658,#657);
#660=EDGE_CURVE('E204',#290,#644,#659,.F.);
#661=ORIENTED_EDGE('',*,*,#660,.T.);
#662=EDGE_LOOP('',(#648,#654,#655,#661));
#663=FACE_BOUND('',#662,.T.);
#664=ADVANCED_FACE('F206',(#663),#637,.T.);
#665=CARTESIAN_POINT('',(34.6351609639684,75.6659708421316,15.875));
#666=DIRECTION('',(0.,0.,1.));
#667=DIRECTION('',(1.,0.,0.));
#668=AXIS2_PLACEMENT_3D('',#665,#666,#667);
#669=PLANE('',#668);
#670=ORIENTED_EDGE('',*,*,#310,.F.);
#671=DIRECTION('',(0.,-1.,0.));
#672=VECTOR('',#671,1.);
#673=CARTESIAN_POINT('',(56.3506599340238,75.6659708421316,15.875));
#674=LINE('',#673,#672);
#675=CARTESIAN_POINT('',(56.3506599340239,7.24658914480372,15.875));
#676=VERTEX_POINT('',#675);
#677=EDGE_CURVE('E231',#301,#676,#674,.F.);
#678=ORIENTED_EDGE('',*,*,#677,.T.);
#679=CARTESIAN_POINT('',(61.4836106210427,4.38530316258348,15.875));
#680=CARTESIAN_POINT('',(60.370936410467,5.00729141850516,15.875));
#681=CARTESIAN_POINT('',(59.2578248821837,5.62849872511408,15.875));
#682=CARTESIAN_POINT('',(57.0305470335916,6.86902112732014,15.875));
#683=CARTESIAN_POINT('',(55.916380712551,7.48833622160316,15.875));
#684=CARTESIAN_POINT('',(53.6868574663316,8.72471928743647,15.875));
#685=CARTESIAN_POINT('',(52.5715005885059,9.34178734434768,15.875));
#686=CARTESIAN_POINT('',(50.3393189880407,10.5732625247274,15.875));
#687=CARTESIAN_POINT('',(49.2224942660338,11.1876696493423,15.875));
#688=CARTESIAN_POINT('',(46.9870508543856,12.4132900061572,15.875));
#689=CARTESIAN_POINT('',(45.8684321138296,13.0245031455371,15.875));
#690=CARTESIAN_POINT('',(43.6290605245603,14.2430010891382,15.875));
#691=CARTESIAN_POINT('',(42.5083076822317,14.850285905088,15.875));
#692=CARTESIAN_POINT('',(40.2641359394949,16.0600183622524,15.875));
#693=CARTESIAN_POINT('',(39.1407169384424,16.662465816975,15.875));
#694=CARTESIAN_POINT('',(37.4531350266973,17.5615455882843,15.875));
#695=CARTESIAN_POINT('',(36.8901958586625,17.8604751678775,15.875));
#696=CARTESIAN_POINT('',(35.7633956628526,18.4565946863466,15.875));
#697=CARTESIAN_POINT('',(35.1995346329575,18.7537846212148,15.875));
#698=CARTESIAN_POINT('',(34.6351609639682,19.05,15.875));
#699=B_SPLINE_CURVE_WITH_KNOTS('',3,(#679,#680,#681,#682,#683,#684,#685,#686,#687,#688,#689,
#690,#691,#692,#693,#694,#695,#696,#697,#698),.UNSPECIFIED.,.F.,.F.,(4,2,2,2,2,2,2,2,2,4),(0.,
3.8241632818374,7.64832921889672,11.4723483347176,15.2963658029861,19.1204937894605,
22.9446103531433,26.7688736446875,28.6810253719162,30.5931815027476),.UNSPECIFIED.);
#700=CARTESIAN_POINT('',(38.4948291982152,17.0063332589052,15.875));
#701=VERTEX_POINT('',#700);
#702=EDGE_CURVE('E224',#676,#701,#699,.T.);
#703=ORIENTED_EDGE('',*,*,#702,.T.);
#704=DIRECTION('',(0.,-1.,0.));
#705=VECTOR('',#704,1.);
#706=CARTESIAN_POINT('',(38.4948291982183,75.6659708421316,15.875));
#707=LINE('',#706,#705);
#708=EDGE_CURVE('E235',#701,#309,#707,.T.);
#709=ORIENTED_EDGE('',*,*,#708,.T.);
#710=EDGE_LOOP('',(#670,#678,#703,#709));
#711=FACE_BOUND('',#710,.T.);
#712=ADVANCED_FACE('F633',(#711),#669,.T.);
#713=CARTESIAN_POINT('',(-31.0657337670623,75.6659708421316,-22.0574292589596));
#714=DIRECTION('',(-0.866025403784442,0.,0.499999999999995));
#715=DIRECTION('',(0.499999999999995,0.,0.866025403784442));
#716=AXIS2_PLACEMENT_3D('',#713,#714,#715);
#717=PLANE('',#716);
#718=CARTESIAN_POINT('',(-31.0657337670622,19.05,-22.0574292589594));
#719=CARTESIAN_POINT('',(-31.3479206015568,18.7537846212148,-22.5461911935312));
#720=CARTESIAN_POINT('',(-31.6298511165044,18.4565946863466,-23.0345091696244));
#721=CARTESIAN_POINT('',(-32.1932512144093,17.8604751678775,-24.0103467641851));
#722=CARTESIAN_POINT('',(-32.4747207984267,17.5615455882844,-24.4978663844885));
#723=CARTESIAN_POINT('',(-33.3185117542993,16.662465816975,-25.9593551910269));
#724=CARTESIAN_POINT('',(-33.8802212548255,16.0600183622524,-26.9322645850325));
#725=CARTESIAN_POINT('',(-35.0023071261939,14.850285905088,-28.8757743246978));
#726=CARTESIAN_POINT('',(-35.5626835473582,14.2430010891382,-29.846374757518));
#727=CARTESIAN_POINT('',(-36.6823693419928,13.0245031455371,-31.7857274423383));
#728=CARTESIAN_POINT('',(-37.2416787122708,12.4132900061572,-32.7544796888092));
#729=CARTESIAN_POINT('',(-38.3594004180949,11.1876696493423,-34.6904304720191));
#730=CARTESIAN_POINT('',(-38.9178127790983,10.5732625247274,-35.6576290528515));
#731=CARTESIAN_POINT('',(-40.0339035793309,9.3417873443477,-37.5907550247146));
#732=CARTESIAN_POINT('',(-40.5915820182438,8.72471928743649,-38.5566824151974));
#733=CARTESIAN_POINT('',(-41.7063436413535,7.48833622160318,-40.4875061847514));
#734=CARTESIAN_POINT('',(-42.2634268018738,6.86902112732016,-41.4524025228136));
#735=CARTESIAN_POINT('',(-43.3770657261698,5.6284987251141,-43.3812817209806));
#736=CARTESIAN_POINT('',(-43.9336214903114,5.00729141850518,-44.3452645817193));
#737=CARTESIAN_POINT('',(-44.4899585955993,4.3853031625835,-45.3088687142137));
#738=B_SPLINE_CURVE_WITH_KNOTS('',3,(#718,#719,#720,#721,#722,#723,#724,#725,#726,#727,#728,
#729,#730,#731,#732,#733,#734,#735,#736,#737),.UNSPECIFIED.,.F.,.F.,(4,2,2,2,2,2,2,2,2,4),(0.,
1.91215613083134,3.82430785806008,7.64857114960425,11.4726877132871,15.2968156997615,
19.12083316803,22.9448522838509,26.7690182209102,30.5931815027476),.UNSPECIFIED.);
#739=CARTESIAN_POINT('',(-32.9955678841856,17.0063332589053,-25.399999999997));
#740=VERTEX_POINT('',#739);
#741=CARTESIAN_POINT('',(-41.9234832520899,7.24658914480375,-40.8636030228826));
#742=VERTEX_POINT('',#741);
#743=EDGE_CURVE('E297',#740,#742,#738,.T.);
#744=ORIENTED_EDGE('',*,*,#743,.T.);
#745=DIRECTION('',(0.,-1.,0.));
#746=VECTOR('',#745,1.);
#747=CARTESIAN_POINT('',(-41.9234832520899,75.6659708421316,-40.8636030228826));
#748=LINE('',#747,#746);
#749=EDGE_CURVE('E537',#742,#394,#748,.T.);
#750=ORIENTED_EDGE('',*,*,#749,.T.);
#751=ORIENTED_EDGE('',*,*,#395,.F.);
#752=DIRECTION('',(0.,-1.,0.));
#753=VECTOR('',#752,1.);
#754=CARTESIAN_POINT('',(-32.9955678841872,75.6659708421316,-25.3999999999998));
#755=LINE('',#754,#753);
#756=EDGE_CURVE('E272',#386,#740,#755,.F.);
#757=ORIENTED_EDGE('',*,*,#756,.T.);
#758=EDGE_LOOP('',(#744,#750,#751,#757));
#759=FACE_BOUND('',#758,.T.);
#760=ADVANCED_FACE('F534',(#759),#717,.T.);
#761=CARTESIAN_POINT('',(0.,75.6659708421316,0.));
#762=DIRECTION('',(0.,-1.,0.));
#763=DIRECTION('',(0.,0.,-1.));
#764=AXIS2_PLACEMENT_3D('',#761,#762,#763);
#765=CYLINDRICAL_SURFACE('',#764,63.5);
#766=CARTESIAN_POINT('',(0.,4.3853031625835,0.));
#767=DIRECTION('',(0.,1.,0.));
#768=DIRECTION('',(0.,0.,1.));
#769=AXIS2_PLACEMENT_3D('',#766,#767,#768);
#770=CIRCLE('',#769,63.5);
#771=CARTESIAN_POINT('',(-40.4713577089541,4.3853031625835,-48.9317811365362));
#772=VERTEX_POINT('',#771);
#773=CARTESIAN_POINT('',(-22.1404866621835,4.3853031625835,-59.5151144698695));
#774=VERTEX_POINT('',#773);
#775=EDGE_CURVE('E652',#772,#774,#770,.F.);
#776=ORIENTED_EDGE('',*,*,#775,.T.);
#777=DIRECTION('',(0.,-1.,0.));
#778=VECTOR('',#777,1.);
#779=CARTESIAN_POINT('',(-22.1404866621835,75.6659708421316,-59.5151144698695));
#780=LINE('',#779,#778);
#781=EDGE_CURVE('E1349',#774,#412,#780,.T.);
#782=ORIENTED_EDGE('',*,*,#781,.T.);
#783=ORIENTED_EDGE('',*,*,#413,.F.);
#784=DIRECTION('',(0.,-1.,0.));
#785=VECTOR('',#784,1.);
#786=CARTESIAN_POINT('',(-40.4713577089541,75.6659708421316,-48.9317811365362));
#787=LINE('',#786,#785);
#788=EDGE_CURVE('E1345',#403,#772,#787,.F.);
#789=ORIENTED_EDGE('',*,*,#788,.T.);
#790=EDGE_LOOP('',(#776,#782,#783,#789));
#791=FACE_BOUND('',#790,.T.);
#792=ADVANCED_FACE('F687',(#791),#765,.T.);
#793=CARTESIAN_POINT('',(-3.56942719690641,75.6659708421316,-37.9324292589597));
#794=DIRECTION('',(0.866025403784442,0.,-0.499999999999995));
#795=DIRECTION('',(-0.499999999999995,0.,-0.866025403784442));
#796=AXIS2_PLACEMENT_3D('',#793,#794,#795);
#797=PLANE('',#796);
#798=ORIENTED_EDGE('',*,*,#430,.F.);
#799=DIRECTION('',(0.,-1.,0.));
#800=VECTOR('',#799,1.);
#801=CARTESIAN_POINT('',(-14.427176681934,75.6659708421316,-56.7386030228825));
#802=LINE('',#801,#800);
#803=CARTESIAN_POINT('',(-14.427176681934,7.24658914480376,-56.7386030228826));
#804=VERTEX_POINT('',#803);
#805=EDGE_CURVE('E1352',#421,#804,#802,.F.);
#806=ORIENTED_EDGE('',*,*,#805,.T.);
#807=CARTESIAN_POINT('',(-16.9936520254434,4.3853031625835,-61.1838687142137));
#808=CARTESIAN_POINT('',(-16.4373149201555,5.00729141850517,-60.2202645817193));
#809=CARTESIAN_POINT('',(-15.8807591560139,5.62849872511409,-59.2562817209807));
#810=CARTESIAN_POINT('',(-14.7671202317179,6.86902112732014,-57.3274025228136));
#811=CARTESIAN_POINT('',(-14.2100370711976,7.48833622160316,-56.3625061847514));
#812=CARTESIAN_POINT('',(-13.0952754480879,8.72471928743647,-54.4316824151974));
#813=CARTESIAN_POINT('',(-12.537597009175,9.34178734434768,-53.4657550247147));
#814=CARTESIAN_POINT('',(-11.4215062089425,10.5732625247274,-51.5326290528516));
#815=CARTESIAN_POINT('',(-10.863093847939,11.1876696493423,-50.5654304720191));
#816=CARTESIAN_POINT('',(-9.74537214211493,12.4132900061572,-48.6294796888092));
#817=CARTESIAN_POINT('',(-9.18606277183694,13.0245031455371,-47.6607274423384));
#818=CARTESIAN_POINT('',(-8.06637697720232,14.2430010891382,-45.7213747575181));
#819=CARTESIAN_POINT('',(-7.50600055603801,14.850285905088,-44.7507743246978));
#820=CARTESIAN_POINT('',(-6.38391468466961,16.0600183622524,-42.8072645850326));
#821=CARTESIAN_POINT('',(-5.8222051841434,16.662465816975,-41.834355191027));
#822=CARTESIAN_POINT('',(-4.97841422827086,17.5615455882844,-40.3728663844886));
#823=CARTESIAN_POINT('',(-4.69694464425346,17.8604751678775,-39.8853467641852));
#824=CARTESIAN_POINT('',(-4.13354454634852,18.4565946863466,-38.9095091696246));
#825=CARTESIAN_POINT('',(-3.85161403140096,18.7537846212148,-38.4211911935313));
#826=CARTESIAN_POINT('',(-3.56942719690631,19.05,-37.9324292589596));
#827=B_SPLINE_CURVE_WITH_KNOTS('',3,(#807,#808,#809,#810,#811,#812,#813,#814,#815,#816,#817,
#818,#819,#820,#821,#822,#823,#824,#825,#826),.UNSPECIFIED.,.F.,.F.,(4,2,2,2,2,2,2,2,2,4),(0.,
3.82416328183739,7.6483292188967,11.4723483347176,15.2963658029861,19.1204937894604,
22.9446103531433,26.7688736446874,28.6810253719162,30.5931815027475),.UNSPECIFIED.);
#828=CARTESIAN_POINT('',(-5.49926131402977,17.0063332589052,-41.2749999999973));
#829=VERTEX_POINT('',#828);
#830=EDGE_CURVE('E287',#804,#829,#827,.T.);
#831=ORIENTED_EDGE('',*,*,#830,.T.);
#832=DIRECTION('',(0.,-1.,0.));
#833=VECTOR('',#832,1.);
#834=CARTESIAN_POINT('',(-5.49926131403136,75.6659708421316,-41.275));
#835=LINE('',#834,#833);
#836=EDGE_CURVE('E1351',#829,#429,#835,.T.);
#837=ORIENTED_EDGE('',*,*,#836,.T.);
#838=EDGE_LOOP('',(#798,#806,#831,#837));
#839=FACE_BOUND('',#838,.T.);
#840=ADVANCED_FACE('F684',(#839),#797,.T.);
#841=CARTESIAN_POINT('',(-3.56942719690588,75.6659708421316,37.9324292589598));
#842=DIRECTION('',(0.866025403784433,0.,0.50000000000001));
#843=DIRECTION('',(0.50000000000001,0.,-0.866025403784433));
#844=AXIS2_PLACEMENT_3D('',#841,#842,#843);
#845=PLANE('',#844);
#846=CARTESIAN_POINT('',(-3.56942719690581,19.05,37.9324292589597));
#847=CARTESIAN_POINT('',(-3.85161403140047,18.7537846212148,38.4211911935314));
#848=CARTESIAN_POINT('',(-4.13354454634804,18.4565946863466,38.9095091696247));
#849=CARTESIAN_POINT('',(-4.69694464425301,17.8604751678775,39.8853467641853));
#850=CARTESIAN_POINT('',(-4.97841422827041,17.5615455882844,40.3728663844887));
#851=CARTESIAN_POINT('',(-5.82220518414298,16.662465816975,41.8343551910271));
#852=CARTESIAN_POINT('',(-6.38391468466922,16.0600183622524,42.8072645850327));
#853=CARTESIAN_POINT('',(-7.50600055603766,14.850285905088,44.7507743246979));
#854=CARTESIAN_POINT('',(-8.06637697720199,14.2430010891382,45.7213747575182));
#855=CARTESIAN_POINT('',(-9.18606277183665,13.0245031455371,47.6607274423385));
#856=CARTESIAN_POINT('',(-9.74537214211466,12.4132900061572,48.6294796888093));
#857=CARTESIAN_POINT('',(-10.8630938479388,11.1876696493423,50.5654304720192));
#858=CARTESIAN_POINT('',(-11.4215062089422,10.5732625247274,51.5326290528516));
#859=CARTESIAN_POINT('',(-12.5375970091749,9.3417873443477,53.4657550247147));
#860=CARTESIAN_POINT('',(-13.0952754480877,8.72471928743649,54.4316824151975));
#861=CARTESIAN_POINT('',(-14.2100370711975,7.48833622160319,56.3625061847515));
#862=CARTESIAN_POINT('',(-14.7671202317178,6.86902112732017,57.3274025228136));
#863=CARTESIAN_POINT('',(-15.8807591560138,5.62849872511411,59.2562817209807));
#864=CARTESIAN_POINT('',(-16.4373149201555,5.00729141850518,60.2202645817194));
#865=CARTESIAN_POINT('',(-16.9936520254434,4.3853031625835,61.1838687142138));
#866=B_SPLINE_CURVE_WITH_KNOTS('',3,(#846,#847,#848,#849,#850,#851,#852,#853,#854,#855,#856,
#857,#858,#859,#860,#861,#862,#863,#864,#865),.UNSPECIFIED.,.F.,.F.,(4,2,2,2,2,2,2,2,2,4),(0.,
1.91215613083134,3.82430785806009,7.64857114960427,11.4726877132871,15.2968156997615,
19.12083316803,22.9448522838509,26.7690182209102,30.5931815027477),.UNSPECIFIED.);
#867=CARTESIAN_POINT('',(-5.49926131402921,17.0063332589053,41.2749999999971));
#868=VERTEX_POINT('',#867);
#869=CARTESIAN_POINT('',(-14.4271766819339,7.24658914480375,56.7386030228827));
#870=VERTEX_POINT('',#869);
#871=EDGE_CURVE('E215',#868,#870,#866,.T.);
#872=ORIENTED_EDGE('',*,*,#871,.T.);
#873=DIRECTION('',(0.,-1.,0.));
#874=VECTOR('',#873,1.);
#875=CARTESIAN_POINT('',(-14.4271766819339,75.6659708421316,56.7386030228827));
#876=LINE('',#875,#874);
#877=EDGE_CURVE('E581',#870,#334,#876,.T.);
#878=ORIENTED_EDGE('',*,*,#877,.T.);
#879=ORIENTED_EDGE('',*,*,#335,.F.);
#880=DIRECTION('',(0.,-1.,0.));
#881=VECTOR('',#880,1.);
#882=CARTESIAN_POINT('',(-5.49926131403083,75.6659708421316,41.2749999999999));
#883=LINE('',#882,#881);
#884=EDGE_CURVE('E580',#326,#868,#883,.F.);
#885=ORIENTED_EDGE('',*,*,#884,.T.);
#886=EDGE_LOOP('',(#872,#878,#879,#885));
#887=FACE_BOUND('',#886,.T.);
#888=ADVANCED_FACE('F681',(#887),#845,.T.);
#889=CARTESIAN_POINT('',(0.,75.6659708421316,0.));
#890=DIRECTION('',(0.,-1.,0.));
#891=DIRECTION('',(0.,0.,-1.));
#892=AXIS2_PLACEMENT_3D('',#889,#890,#891);
#893=CYLINDRICAL_SURFACE('',#892,63.5);
#894=CARTESIAN_POINT('',(0.,4.38530316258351,0.));
#895=DIRECTION('',(0.,1.,0.));
#896=DIRECTION('',(0.,0.,1.));
#897=AXIS2_PLACEMENT_3D('',#894,#895,#896);
#898=CIRCLE('',#897,63.5);
#899=CARTESIAN_POINT('',(-22.1404866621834,4.38530316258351,59.5151144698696));
#900=VERTEX_POINT('',#899);
#901=CARTESIAN_POINT('',(-40.4713577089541,4.38530316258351,48.9317811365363));
#902=VERTEX_POINT('',#901);
#903=EDGE_CURVE('E661',#900,#902,#898,.F.);
#904=ORIENTED_EDGE('',*,*,#903,.T.);
#905=DIRECTION('',(0.,-1.,0.));
#906=VECTOR('',#905,1.);
#907=CARTESIAN_POINT('',(-40.4713577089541,75.6659708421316,48.9317811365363));
#908=LINE('',#907,#906);
#909=EDGE_CURVE('E543',#902,#352,#908,.T.);
#910=ORIENTED_EDGE('',*,*,#909,.T.);
#911=ORIENTED_EDGE('',*,*,#353,.F.);
#912=DIRECTION('',(0.,-1.,0.));
#913=VECTOR('',#912,1.);
#914=CARTESIAN_POINT('',(-22.1404866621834,75.6659708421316,59.5151144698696));
#915=LINE('',#914,#913);
#916=EDGE_CURVE('E542',#343,#900,#915,.F.);
#917=ORIENTED_EDGE('',*,*,#916,.T.);
#918=EDGE_LOOP('',(#904,#910,#911,#917));
#919=FACE_BOUND('',#918,.T.);
#920=ADVANCED_FACE('F677',(#919),#893,.T.);
#921=CARTESIAN_POINT('',(-31.065733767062,75.6659708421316,22.05742925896));
#922=DIRECTION('',(-0.866025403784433,0.,-0.50000000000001));
#923=DIRECTION('',(-0.50000000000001,0.,0.866025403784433));
#924=AXIS2_PLACEMENT_3D('',#921,#922,#923);
#925=PLANE('',#924);
#926=ORIENTED_EDGE('',*,*,#370,.F.);
#927=DIRECTION('',(0.,-1.,0.));
#928=VECTOR('',#927,1.);
#929=CARTESIAN_POINT('',(-41.9234832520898,75.6659708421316,40.8636030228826));
#930=LINE('',#929,#928);
#931=CARTESIAN_POINT('',(-41.9234832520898,7.24658914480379,40.8636030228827));
#932=VERTEX_POINT('',#931);
#933=EDGE_CURVE('E551',#361,#932,#930,.F.);
#934=ORIENTED_EDGE('',*,*,#933,.T.);
#935=CARTESIAN_POINT('',(-44.4899585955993,4.38530316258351,45.3088687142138));
#936=CARTESIAN_POINT('',(-43.9336214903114,5.00729141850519,44.3452645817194));
#937=CARTESIAN_POINT('',(-43.3770657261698,5.62849872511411,43.3812817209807));
#938=CARTESIAN_POINT('',(-42.2634268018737,6.86902112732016,41.4524025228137));
#939=CARTESIAN_POINT('',(-41.7063436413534,7.48833622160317,40.4875061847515));
#940=CARTESIAN_POINT('',(-40.5915820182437,8.72471928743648,38.5566824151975));
#941=CARTESIAN_POINT('',(-40.0339035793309,9.34178734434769,37.5907550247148));
#942=CARTESIAN_POINT('',(-38.9178127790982,10.5732625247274,35.6576290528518));
#943=CARTESIAN_POINT('',(-38.3594004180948,11.1876696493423,34.6904304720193));
#944=CARTESIAN_POINT('',(-37.2416787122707,12.4132900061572,32.7544796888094));
#945=CARTESIAN_POINT('',(-36.6823693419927,13.0245031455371,31.7857274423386));
#946=CARTESIAN_POINT('',(-35.562683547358,14.2430010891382,29.8463747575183));
#947=CARTESIAN_POINT('',(-35.0023071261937,14.850285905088,28.8757743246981));
#948=CARTESIAN_POINT('',(-33.8802212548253,16.0600183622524,26.9322645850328));
#949=CARTESIAN_POINT('',(-33.318511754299,16.662465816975,25.9593551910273));
#950=CARTESIAN_POINT('',(-32.4747207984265,17.5615455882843,24.497866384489));
#951=CARTESIAN_POINT('',(-32.1932512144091,17.8604751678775,24.0103467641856));
#952=CARTESIAN_POINT('',(-31.6298511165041,18.4565946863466,23.0345091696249));
#953=CARTESIAN_POINT('',(-31.3479206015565,18.7537846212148,22.5461911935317));
#954=CARTESIAN_POINT('',(-31.0657337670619,19.05,22.0574292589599));
#955=B_SPLINE_CURVE_WITH_KNOTS('',3,(#935,#936,#937,#938,#939,#940,#941,#942,#943,#944,#945,
#946,#947,#948,#949,#950,#951,#952,#953,#954),.UNSPECIFIED.,.F.,.F.,(4,2,2,2,2,2,2,2,2,4),(0.,
3.82416328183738,7.64832921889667,11.4723483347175,15.296365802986,19.1204937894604,
22.9446103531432,26.7688736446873,28.6810253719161,30.5931815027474),.UNSPECIFIED.);
#956=CARTESIAN_POINT('',(-32.9955678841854,17.0063332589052,25.3999999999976));
#957=VERTEX_POINT('',#956);
#958=EDGE_CURVE('E601',#932,#957,#955,.T.);
#959=ORIENTED_EDGE('',*,*,#958,.T.);
#960=DIRECTION('',(0.,-1.,0.));
#961=VECTOR('',#960,1.);
#962=CARTESIAN_POINT('',(-32.995567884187,75.6659708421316,25.4000000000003));
#963=LINE('',#962,#961);
#964=EDGE_CURVE('E548',#957,#369,#963,.T.);
#965=ORIENTED_EDGE('',*,*,#964,.T.);
#966=EDGE_LOOP('',(#926,#934,#959,#965));
#967=FACE_BOUND('',#966,.T.);
#968=ADVANCED_FACE('F600',(#967),#925,.T.);
#969=CARTESIAN_POINT('',(0.,4.38530316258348,0.));
#970=DIRECTION('',(0.,-1.,0.));
#971=DIRECTION('',(0.,0.,-1.));
#972=AXIS2_PLACEMENT_3D('',#969,#970,#971);
#973=CONICAL_SURFACE('',#972,63.5,1.0471975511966);
#974=ORIENTED_EDGE('',*,*,#702,.F.);
#975=CARTESIAN_POINT('',(56.3506599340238,7.24658914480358,15.875));
#976=CARTESIAN_POINT('',(56.5405521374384,7.14105785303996,15.8750059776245));
#977=CARTESIAN_POINT('',(56.7310247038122,7.03650755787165,15.8664814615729));
#978=CARTESIAN_POINT('',(57.1119171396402,6.82998421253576,15.8321034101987));
#979=CARTESIAN_POINT('',(57.3023369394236,6.7280124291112,15.8062415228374));
#980=CARTESIAN_POINT('',(57.6828542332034,6.52676707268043,15.7367138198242));
#981=CARTESIAN_POINT('',(57.8729430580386,6.4275131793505,15.6929429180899));
#982=CARTESIAN_POINT('',(58.2501677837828,6.23306747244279,15.5874023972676));
#983=CARTESIAN_POINT('',(58.437304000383,6.1378752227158,15.5256347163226));
#984=CARTESIAN_POINT('',(58.8077257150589,5.95196241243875,15.3837371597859));
#985=CARTESIAN_POINT('',(58.9909952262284,5.86125888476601,15.30354302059));
#986=CARTESIAN_POINT('',(59.3511743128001,5.68553264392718,15.1249812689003));
#987=CARTESIAN_POINT('',(59.5280873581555,5.60050680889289,15.0266237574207));
#988=CARTESIAN_POINT('',(59.8734689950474,5.43707603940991,14.8121125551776));
#989=CARTESIAN_POINT('',(60.0419536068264,5.35865833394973,14.6959944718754));
#990=CARTESIAN_POINT('',(60.368883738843,5.20912001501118,14.4462471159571));
#991=CARTESIAN_POINT('',(60.5273308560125,5.13799823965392,14.3126206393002));
#992=CARTESIAN_POINT('',(60.8165251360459,5.01078954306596,14.043131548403));
#993=CARTESIAN_POINT('',(60.9484467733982,4.95390876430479,13.9089025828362));
#994=CARTESIAN_POINT('',(61.2010666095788,4.84733849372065,13.627653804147));
#995=CARTESIAN_POINT('',(61.3217668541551,4.79764769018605,13.4806363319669));
#996=CARTESIAN_POINT('',(61.5503974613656,4.70607277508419,13.1748829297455));
#997=CARTESIAN_POINT('',(61.6583369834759,4.66418305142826,13.0161555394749));
#998=CARTESIAN_POINT('',(61.8601211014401,4.58871078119,12.6881303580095));
#999=CARTESIAN_POINT('',(61.9539686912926,4.5551264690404,12.5188348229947));
#1000=CARTESIAN_POINT('',(62.1083374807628,4.50280662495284,12.2073975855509));
#1001=CARTESIAN_POINT('',(62.1717289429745,4.48243532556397,12.066942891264));
#1002=CARTESIAN_POINT('',(62.288323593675,4.44736801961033,11.7812032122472));
#1003=CARTESIAN_POINT('',(62.3415290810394,4.43267073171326,11.6359193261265));
#1004=CARTESIAN_POINT('',(62.4373980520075,4.40906232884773,11.341090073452));
#1005=CARTESIAN_POINT('',(62.480037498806,4.40016433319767,11.1915358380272));
#1006=CARTESIAN_POINT('',(62.5542985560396,4.38827851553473,10.8894230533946));
#1007=CARTESIAN_POINT('',(62.5859157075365,4.38529308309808,10.7368633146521));
#1008=CARTESIAN_POINT('',(62.6118443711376,4.38530316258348,10.5833333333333));
#1009=B_SPLINE_CURVE_WITH_KNOTS('',3,(#975,#976,#977,#978,#979,#980,#981,#982,#983,#984,#985,
#986,#987,#988,#989,#990,#991,#992,#993,#994,#995,#996,#997,#998,#999,#1000,#1001,#1002,#1003,
#1004,#1005,#1006,#1007,#1008),.UNSPECIFIED.,.F.,.F.,(4,2,2,2,2,2,2,2,2,2,2,2,2,2,2,2,4),(0.,
0.651614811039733,1.30354375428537,1.959354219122,2.61509408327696,3.27315656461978,
3.93085418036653,4.58725008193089,5.24354128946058,5.83255087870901,6.42145287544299,
7.00992956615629,7.59828105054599,8.06411139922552,8.5298364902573,8.99661153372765,
9.46357518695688),.UNSPECIFIED.);
#1010=EDGE_CURVE('E223',#676,#646,#1009,.T.);
#1011=ORIENTED_EDGE('',*,*,#1010,.T.);
#1012=ORIENTED_EDGE('',*,*,#647,.F.);
#1013=CARTESIAN_POINT('',(62.6118443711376,4.38530316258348,-10.5833333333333));
#1014=CARTESIAN_POINT('',(62.5845617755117,4.3852906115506,-10.7449057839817));
#1015=CARTESIAN_POINT('',(62.5509734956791,4.388598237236,-10.9054026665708));
#1016=CARTESIAN_POINT('',(62.4715976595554,4.40176120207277,-11.223033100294));
#1017=CARTESIAN_POINT('',(62.4258133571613,4.41161479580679,-11.3801675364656));
#1018=CARTESIAN_POINT('',(62.3226254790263,4.43773086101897,-11.6894001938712));
#1019=CARTESIAN_POINT('',(62.265263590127,4.45397053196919,-11.8415142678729));
#1020=CARTESIAN_POINT('',(62.1393837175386,4.49268791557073,-12.14023256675));
#1021=CARTESIAN_POINT('',(62.0708654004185,4.51516581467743,-12.2868366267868));
#1022=CARTESIAN_POINT('',(61.9233959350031,4.56611560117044,-12.5734536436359));
#1023=CARTESIAN_POINT('',(61.8444532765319,4.59458262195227,-12.7134718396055));
#1024=CARTESIAN_POINT('',(61.6768085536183,4.65726272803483,-12.9862541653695));
#1025=CARTESIAN_POINT('',(61.5881028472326,4.6914779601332,-13.1190155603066));
#1026=CARTESIAN_POINT('',(61.4017503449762,4.76534552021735,-13.3765255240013));
#1027=CARTESIAN_POINT('',(61.304102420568,4.80499853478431,-13.5012730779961));
#1028=CARTESIAN_POINT('',(61.100682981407,4.88942001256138,-13.7421850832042));
#1029=CARTESIAN_POINT('',(60.9949083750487,4.9341904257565,-13.8583462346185));
#1030=CARTESIAN_POINT('',(60.7715710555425,5.03044920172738,-14.0861983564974));
#1031=CARTESIAN_POINT('',(60.6537012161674,5.08213934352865,-14.1975033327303));
#1032=CARTESIAN_POINT('',(60.4110639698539,5.1902799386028,-14.4098384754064));
#1033=CARTESIAN_POINT('',(60.2862940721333,5.24673211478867,-14.5108648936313));
#1034=CARTESIAN_POINT('',(59.903062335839,5.42262710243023,-14.7980151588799));
#1035=CARTESIAN_POINT('',(59.6355621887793,5.54865846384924,-14.9683274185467));
#1036=CARTESIAN_POINT('',(59.0546977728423,5.82910706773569,-15.2809468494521));
#1037=CARTESIAN_POINT('',(58.7394841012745,5.98511807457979,-15.4183335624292));
#1038=CARTESIAN_POINT('',(58.0974141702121,6.31057933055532,-15.6394552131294));
#1039=CARTESIAN_POINT('',(57.7705576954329,6.48002982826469,-15.7231891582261));
#1040=CARTESIAN_POINT('',(57.2602338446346,6.75052038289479,-15.8122301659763));
#1041=CARTESIAN_POINT('',(57.0779966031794,6.84827313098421,-15.8358636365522));
#1042=CARTESIAN_POINT('',(56.7139064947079,7.0459078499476,-15.8672240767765));
#1043=CARTESIAN_POINT('',(56.5320538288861,7.14578377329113,-15.8749913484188));
#1044=CARTESIAN_POINT('',(56.3506599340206,7.24658914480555,-15.875));
#1045=B_SPLINE_CURVE_WITH_KNOTS('',3,(#1013,#1014,#1015,#1016,#1017,#1018,#1019,#1020,#1021,
#1022,#1023,#1024,#1025,#1026,#1027,#1028,#1029,#1030,#1031,#1032,#1033,#1034,#1035,#1036,#1037,
#1038,#1039,#1040,#1041,#1042,#1043,#1044),.UNSPECIFIED.,.F.,.F.,(4,2,2,2,2,2,2,2,2,2,2,2,2,2,2,
4),(0.,0.491407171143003,0.982683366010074,1.47222123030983,1.96177372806,2.45092995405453,
2.94026927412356,3.42967043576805,3.91925870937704,4.42917957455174,4.93928572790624,
5.95898553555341,7.0873815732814,8.21579848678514,8.83969026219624,9.4619952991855),.UNSPECIFIED.);
#1046=EDGE_CURVE('E220',#644,#614,#1045,.T.);
#1047=ORIENTED_EDGE('',*,*,#1046,.T.);
#1048=ORIENTED_EDGE('',*,*,#615,.F.);
#1049=CARTESIAN_POINT('',(38.4948291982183,17.0063332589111,-15.875));
#1050=CARTESIAN_POINT('',(38.3161534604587,17.1016949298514,-15.8749991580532));
#1051=CARTESIAN_POINT('',(38.1367162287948,17.1957173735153,-15.8825422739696));
#1052=CARTESIAN_POINT('',(37.7772423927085,17.3803354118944,-15.9130960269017));
#1053=CARTESIAN_POINT('',(37.5972054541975,17.4709285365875,-15.9361175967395));
#1054=CARTESIAN_POINT('',(37.2359811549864,17.6486537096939,-15.998306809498));
#1055=CARTESIAN_POINT('',(37.0547994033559,17.7357440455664,-16.0376277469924));
#1056=CARTESIAN_POINT('',(36.6942130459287,17.9045973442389,-16.1327870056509));
#1057=CARTESIAN_POINT('',(36.5148089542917,17.9863588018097,-16.1886299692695));
#1058=CARTESIAN_POINT('',(36.1582466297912,18.143908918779,-16.3174619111));
#1059=CARTESIAN_POINT('',(35.9811058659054,18.2196627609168,-16.3905422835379));
#1060=CARTESIAN_POINT('',(35.6316456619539,18.3635515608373,-16.5538559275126));
#1061=CARTESIAN_POINT('',(35.4593266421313,18.4316858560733,-16.6440906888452));
#1062=CARTESIAN_POINT('',(35.1223346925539,18.5587193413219,-16.8410757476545));
#1063=CARTESIAN_POINT('',(34.9576220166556,18.6176715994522,-16.9477234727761));
#1064=CARTESIAN_POINT('',(34.636792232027,18.7255697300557,-17.1775312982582));
#1065=CARTESIAN_POINT('',(34.4806688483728,18.774522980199,-17.3006791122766));
#1066=CARTESIAN_POINT('',(34.2000431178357,18.8552466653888,-17.544520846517));
#1067=CARTESIAN_POINT('',(34.074168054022,18.8884615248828,-17.6631600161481));
#1068=CARTESIAN_POINT('',(33.8315998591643,18.9459986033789,-17.9114282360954));
#1069=CARTESIAN_POINT('',(33.7149044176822,18.9703230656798,-18.041054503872));
#1070=CARTESIAN_POINT('',(33.4906406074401,19.0097970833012,-18.3119627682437));
#1071=CARTESIAN_POINT('',(33.3831958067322,19.0248352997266,-18.4533639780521));
#1072=CARTESIAN_POINT('',(33.2309733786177,19.0399135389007,-18.6722201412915));
#1073=CARTESIAN_POINT('',(33.1816973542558,19.0436931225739,-18.7463429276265));
#1074=CARTESIAN_POINT('',(33.086264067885,19.0487369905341,-18.8966596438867));
#1075=CARTESIAN_POINT('',(33.0401070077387,19.050001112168,-18.9728537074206));
#1076=CARTESIAN_POINT('',(32.9955678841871,19.0499999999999,-19.0500000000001));
#1077=B_SPLINE_CURVE_WITH_KNOTS('',3,(#1049,#1050,#1051,#1052,#1053,#1054,#1055,#1056,#1057,
#1058,#1059,#1060,#1061,#1062,#1063,#1064,#1065,#1066,#1067,#1068,#1069,#1070,#1071,#1072,#1073,
#1074,#1075,#1076),.UNSPECIFIED.,.F.,.F.,(4,2,2,2,2,2,2,2,2,2,2,2,2,4),(0.,0.607509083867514,
1.215447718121,1.82923858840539,2.44320208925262,3.06049710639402,3.67784575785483,
4.29148222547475,4.90466427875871,5.43229625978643,5.95979501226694,6.49350136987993,
6.76066500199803,7.02784590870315),.UNSPECIFIED.);
#1078=EDGE_CURVE('E339',#612,#250,#1077,.T.);
#1079=ORIENTED_EDGE('',*,*,#1078,.T.);
#1080=ORIENTED_EDGE('',*,*,#251,.F.);
#1081=CARTESIAN_POINT('',(32.9955678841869,19.05,19.0499999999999));
#1082=CARTESIAN_POINT('',(33.0744694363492,19.0500257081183,18.9132752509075));
#1083=CARTESIAN_POINT('',(33.1585141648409,19.0460361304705,18.7795387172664));
#1084=CARTESIAN_POINT('',(33.3360325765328,19.030218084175,18.5190536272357));
#1085=CARTESIAN_POINT('',(33.4295018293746,19.0183932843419,18.3923018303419));
#1086=CARTESIAN_POINT('',(33.6245530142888,18.9871816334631,18.1473389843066));
#1087=CARTESIAN_POINT('',(33.7260878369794,18.9678364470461,18.0290850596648));
#1088=CARTESIAN_POINT('',(33.9367990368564,18.921925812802,17.8010928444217));
#1089=CARTESIAN_POINT('',(34.0459759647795,18.8953598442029,17.6913551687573));
#1090=CARTESIAN_POINT('',(34.2708224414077,18.8354890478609,17.4811721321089));
#1091=CARTESIAN_POINT('',(34.3864799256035,18.8021964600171,17.3807103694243));
#1092=CARTESIAN_POINT('',(34.6235333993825,18.7293394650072,17.1892458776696));
#1093=CARTESIAN_POINT('',(34.7449315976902,18.6897726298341,17.098246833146));
#1094=CARTESIAN_POINT('',(35.1165373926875,18.5623831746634,16.8397812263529));
#1095=CARTESIAN_POINT('',(35.3741033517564,18.4658859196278,16.6868951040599));
#1096=CARTESIAN_POINT('',(35.919899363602,18.2469879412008,16.4118956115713));
#1097=CARTESIAN_POINT('',(36.209017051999,18.123254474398,16.292653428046));
#1098=CARTESIAN_POINT('',(36.7947421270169,17.8594814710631,16.0990462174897));
#1099=CARTESIAN_POINT('',(37.0913511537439,17.7194383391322,16.0246911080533));
#1100=CARTESIAN_POINT('',(37.5734354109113,17.4828284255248,15.9393979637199));
#1101=CARTESIAN_POINT('',(37.7584704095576,17.389875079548,15.9151081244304));
#1102=CARTESIAN_POINT('',(38.1275266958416,17.2005302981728,15.8829381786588));
#1103=CARTESIAN_POINT('',(38.3115493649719,17.1041497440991,15.8750101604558));
#1104=CARTESIAN_POINT('',(38.4948291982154,17.006333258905,15.875));
#1105=B_SPLINE_CURVE_WITH_KNOTS('',3,(#1081,#1082,#1083,#1084,#1085,#1086,#1087,#1088,#1089,
#1090,#1091,#1092,#1093,#1094,#1095,#1096,#1097,#1098,#1099,#1100,#1101,#1102,#1103,#1104),
.UNSPECIFIED.,.F.,.F.,(4,2,2,2,2,2,2,2,2,2,2,4),(0.,0.473386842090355,0.946552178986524,
1.41713259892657,1.88774696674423,2.3575125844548,2.82746043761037,3.76757387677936,
4.77291677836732,5.7784817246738,6.40333841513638,7.02636274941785),.UNSPECIFIED.);
#1106=EDGE_CURVE('E346',#40,#701,#1105,.T.);
#1107=ORIENTED_EDGE('',*,*,#1106,.T.);
#1108=EDGE_LOOP('',(#974,#1011,#1012,#1047,#1048,#1079,#1080,#1107));
#1109=FACE_BOUND('',#1108,.T.);
#1110=ADVANCED_FACE('F218',(#1109),#973,.T.);
#1111=CARTESIAN_POINT('',(0.,4.3853031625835,0.));
#1112=DIRECTION('',(0.,-1.,0.));
#1113=DIRECTION('',(0.,0.,-1.));
#1114=AXIS2_PLACEMENT_3D('',#1111,#1112,#1113);
#1115=CONICAL_SURFACE('',#1114,63.5,1.0471975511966);
#1116=ORIENTED_EDGE('',*,*,#830,.F.);
#1117=CARTESIAN_POINT('',(-14.427176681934,7.24658914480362,-56.7386030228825));
#1118=CARTESIAN_POINT('',(-14.5221176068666,7.14105785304,-56.9030574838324));
#1119=CARTESIAN_POINT('',(-14.6247363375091,7.03650755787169,-57.0637493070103));
#1120=CARTESIAN_POINT('',(-14.8449548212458,6.8299842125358,-57.3764228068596));
#1121=CARTESIAN_POINT('',(-14.9625617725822,6.72801242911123,-57.528400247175));
#1122=CARTESIAN_POINT('',(-15.2130331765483,6.52676707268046,-57.8231740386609));
#1123=CARTESIAN_POINT('',(-15.3459843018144,6.42751317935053,-57.9659103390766));
#1124=CARTESIAN_POINT('',(-15.6259974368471,6.23306747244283,-58.2398262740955));
#1125=CARTESIAN_POINT('',(-15.7730579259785,6.13787522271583,-58.371007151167));
#1126=CARTESIAN_POINT('',(-16.0811556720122,5.95196241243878,-58.6208529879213));
#1127=CARTESIAN_POINT('',(-16.2422405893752,5.86125888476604,-58.7394719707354));
#1128=CARTESIAN_POINT('',(-16.5769691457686,5.68553264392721,-58.9621153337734));
#1129=CARTESIAN_POINT('',(-16.7506057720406,5.60050680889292,-59.0661477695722));
#1130=CARTESIAN_POINT('',(-17.1090687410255,5.43707603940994,-59.2580014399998));
#1131=CARTESIAN_POINT('',(-17.2938722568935,5.35865833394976,-59.3458543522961));
#1132=CARTESIAN_POINT('',(-17.6736248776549,5.2091200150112,-59.5041104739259));
#1133=CARTESIAN_POINT('',(-17.8685723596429,5.13799823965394,-59.5745164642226));
#1134=CARTESIAN_POINT('',(-18.2465538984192,5.01078954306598,-59.6902215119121));
#1135=CARTESIAN_POINT('',(-18.4287604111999,4.95390876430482,-59.7373545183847));
#1136=CARTESIAN_POINT('',(-18.7986389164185,4.84733849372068,-59.8155053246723));
#1137=CARTESIAN_POINT('',(-18.9863099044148,4.79764769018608,-59.8465260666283));
#1138=CARTESIAN_POINT('',(-19.3654154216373,4.70607277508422,-59.8916492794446));
#1139=CARTESIAN_POINT('',(-19.5568471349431,4.66418305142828,-59.9057639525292));
#1140=CARTESIAN_POINT('',(-19.9418173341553,4.58871078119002,-59.9165015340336));
#1141=CARTESIAN_POINT('',(-20.1353553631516,4.55512646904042,-59.9131281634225));
#1142=CARTESIAN_POINT('',(-20.4822523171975,4.50280662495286,-59.8910968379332));
#1143=CARTESIAN_POINT('',(-20.6355853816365,4.48243532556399,-59.8757681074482));
#1144=CARTESIAN_POINT('',(-20.9413405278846,4.44736801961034,-59.8338721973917));
#1145=CARTESIAN_POINT('',(-21.0937628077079,4.43267073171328,-59.8073075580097));
#1146=CARTESIAN_POINT('',(-21.3970269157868,4.40906232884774,-59.7429178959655));
#1147=CARTESIAN_POINT('',(-21.5478644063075,4.40016433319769,-59.7050676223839));
#1148=CARTESIAN_POINT('',(-21.8466322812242,4.38827851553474,-59.6183231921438));
#1149=CARTESIAN_POINT('',(-21.9945614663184,4.38529308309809,-59.5694245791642));
#1150=CARTESIAN_POINT('',(-22.1404866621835,4.3853031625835,-59.5151144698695));
#1151=B_SPLINE_CURVE_WITH_KNOTS('',3,(#1117,#1118,#1119,#1120,#1121,#1122,#1123,#1124,#1125,
#1126,#1127,#1128,#1129,#1130,#1131,#1132,#1133,#1134,#1135,#1136,#1137,#1138,#1139,#1140,#1141,
#1142,#1143,#1144,#1145,#1146,#1147,#1148,#1149,#1150),.UNSPECIFIED.,.F.,.F.,(4,2,2,2,2,2,2,2,2,
2,2,2,2,2,2,2,4),(0.,0.651614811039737,1.30354375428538,1.95935421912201,2.61509408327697,
3.27315656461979,3.93085418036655,4.58725008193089,5.24354128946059,5.83255087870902,
6.421452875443,7.00992956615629,7.598281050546,8.06411139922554,8.52983649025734,
8.9966115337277,9.46357518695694),.UNSPECIFIED.);
#1152=EDGE_CURVE('E266',#804,#774,#1151,.T.);
#1153=ORIENTED_EDGE('',*,*,#1152,.T.);
#1154=ORIENTED_EDGE('',*,*,#775,.F.);
#1155=CARTESIAN_POINT('',(-40.4713577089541,4.3853031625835,-48.9317811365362));
#1156=CARTESIAN_POINT('',(-40.5976422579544,4.3852906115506,-48.8273674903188));
#1157=CARTESIAN_POINT('',(-40.7198424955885,4.38859823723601,-48.7180307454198));
#1158=CARTESIAN_POINT('',(-40.955230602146,4.40176120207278,-48.4904740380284));
#1159=CARTESIAN_POINT('',(-41.0684208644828,4.41161479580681,-48.3722564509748));
#1160=CARTESIAN_POINT('',(-41.2846302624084,4.43773086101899,-48.1282767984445));
#1161=CARTESIAN_POINT('',(-41.3876839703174,4.4539705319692,-48.0025429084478));
#1162=CARTESIAN_POINT('',(-41.5834416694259,4.49268791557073,-47.7441685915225));
#1163=CARTESIAN_POINT('',(-41.6761453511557,4.51516581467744,-47.6115279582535));
#1164=CARTESIAN_POINT('',(-41.8506282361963,4.56611560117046,-47.3405071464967));
#1165=CARTESIAN_POINT('',(-41.9324162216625,4.59458262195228,-47.2021317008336));
#1166=CARTESIAN_POINT('',(-42.0848302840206,4.65726272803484,-46.9205559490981));
#1167=CARTESIAN_POINT('',(-42.1554521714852,4.69147796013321,-46.7773538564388));
#1168=CARTESIAN_POINT('',(-42.2852860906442,4.76534552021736,-46.4872128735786));
#1169=CARTESIAN_POINT('',(-42.3444966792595,4.80499853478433,-46.3402735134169));
#1170=CARTESIAN_POINT('',(-42.4514228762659,4.88942001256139,-46.0436511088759));
#1171=CARTESIAN_POINT('',(-42.4991340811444,4.93419042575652,-45.8939670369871));
#1172=CARTESIAN_POINT('',(-42.5847911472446,5.0304492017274,-45.5866251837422));
#1173=CARTESIAN_POINT('',(-42.6222491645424,5.08213934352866,-45.4288944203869));
#1174=CARTESIAN_POINT('',(-42.6848181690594,5.19027993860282,-45.1125968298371));
#1175=CARTESIAN_POINT('',(-42.7099246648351,5.24673211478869,-44.9540297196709));
#1176=CARTESIAN_POINT('',(-42.7669882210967,5.42262710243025,-44.4785661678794));
#1177=CARTESIAN_POINT('',(-42.7807328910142,5.54865846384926,-44.1617481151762));
#1178=CARTESIAN_POINT('',(-42.7610370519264,5.82910706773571,-43.5023950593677));
#1179=CARTESIAN_POINT('',(-42.7224105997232,5.98511807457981,-43.1607186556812));
#1180=CARTESIAN_POINT('',(-42.5928726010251,6.31057933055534,-42.494108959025));
#1181=CARTESIAN_POINT('',(-42.5019600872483,6.4800298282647,-42.1691759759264));
#1182=CARTESIAN_POINT('',(-42.3239099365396,6.75052038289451,-41.6827020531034));
#1183=CARTESIAN_POINT('',(-42.2532585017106,6.84827313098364,-41.5130632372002));
#1184=CARTESIAN_POINT('',(-42.0983723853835,7.04590784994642,-41.182071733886));
#1185=CARTESIAN_POINT('',(-42.0141727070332,7.14578377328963,-41.0206990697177));
#1186=CARTESIAN_POINT('',(-41.9234832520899,7.24658914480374,-40.8636030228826));
#1187=B_SPLINE_CURVE_WITH_KNOTS('',3,(#1155,#1156,#1157,#1158,#1159,#1160,#1161,#1162,#1163,
#1164,#1165,#1166,#1167,#1168,#1169,#1170,#1171,#1172,#1173,#1174,#1175,#1176,#1177,#1178,#1179,
#1180,#1181,#1182,#1183,#1184,#1185,#1186),.UNSPECIFIED.,.F.,.F.,(4,2,2,2,2,2,2,2,2,2,2,2,2,2,2,
4),(0.,0.49140717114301,0.982683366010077,1.47222123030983,1.96177372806,2.45092995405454,
2.94026927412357,3.42967043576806,3.91925870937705,4.42917957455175,4.93928572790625,
5.95898553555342,7.0873815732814,8.21579848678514,8.83969026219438,9.46199529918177),.UNSPECIFIED.);
#1188=EDGE_CURVE('E273',#772,#742,#1187,.T.);
#1189=ORIENTED_EDGE('',*,*,#1188,.T.);
#1190=ORIENTED_EDGE('',*,*,#743,.F.);
#1191=CARTESIAN_POINT('',(-32.9955678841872,17.0063332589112,-25.3999999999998));
#1192=CARTESIAN_POINT('',(-32.9062292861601,17.1016949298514,-25.2452626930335));
#1193=CARTESIAN_POINT('',(-32.8230432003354,17.1957173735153,-25.0860939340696));
#1194=CARTESIAN_POINT('',(-32.6697666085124,17.3803354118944,-24.7595035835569));
#1195=CARTESIAN_POINT('',(-32.5996854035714,17.4709285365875,-24.5920762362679));
#1196=CARTESIAN_POINT('',(-32.472930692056,17.6486537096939,-24.2481522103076));
#1197=CARTESIAN_POINT('',(-32.4163927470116,17.7357440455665,-24.0715837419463));
#1198=CARTESIAN_POINT('',(-32.3185099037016,17.904597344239,-23.711727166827));
#1199=CARTESIAN_POINT('',(-32.2771692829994,17.9863588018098,-23.5284371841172));
#1200=CARTESIAN_POINT('',(-32.2104598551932,18.1439089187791,-23.1552291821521));
#1201=CARTESIAN_POINT('',(-32.1851789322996,18.2196627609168,-22.9652805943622));
#1202=CARTESIAN_POINT('',(-32.1518825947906,18.3635515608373,-22.5809823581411));
#1203=CARTESIAN_POINT('',(-32.1438686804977,18.4316858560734,-22.3866323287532));
#1204=CARTESIAN_POINT('',(-32.1459667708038,18.5587193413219,-21.9962962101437));
#1205=CARTESIAN_POINT('',(-32.1559700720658,18.6176715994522,-21.8003269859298));
#1206=CARTESIAN_POINT('',(-32.1945745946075,18.7255697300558,-21.4075763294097));
#1207=CARTESIAN_POINT('',(-32.2231620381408,18.774522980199,-21.2107956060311));
#1208=CARTESIAN_POINT('',(-32.2940223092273,18.8552466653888,-20.8458457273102));
#1209=CARTESIAN_POINT('',(-32.3338293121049,18.8884615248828,-20.677515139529));
#1210=CARTESIAN_POINT('',(-32.4275518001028,18.9459986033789,-20.3433108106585));
#1211=CARTESIAN_POINT('',(-32.481463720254,18.9703230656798,-20.1774364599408));
#1212=CARTESIAN_POINT('',(-32.603945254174,19.0097970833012,-19.8477641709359));
#1213=CARTESIAN_POINT('',(-32.6726798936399,19.0248352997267,-19.684013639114));
#1214=CARTESIAN_POINT('',(-32.7861036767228,19.0399135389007,-19.4427570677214));
#1215=CARTESIAN_POINT('',(-32.8256578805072,19.0436931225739,-19.3630213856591));
#1216=CARTESIAN_POINT('',(-32.9081193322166,19.0487369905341,-19.2052153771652));
#1217=CARTESIAN_POINT('',(-32.9510267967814,19.0500011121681,-19.1271451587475));
#1218=CARTESIAN_POINT('',(-32.9955678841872,19.0499999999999,-19.0499999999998));
#1219=B_SPLINE_CURVE_WITH_KNOTS('',3,(#1191,#1192,#1193,#1194,#1195,#1196,#1197,#1198,#1199,
#1200,#1201,#1202,#1203,#1204,#1205,#1206,#1207,#1208,#1209,#1210,#1211,#1212,#1213,#1214,#1215,
#1216,#1217,#1218),.UNSPECIFIED.,.F.,.F.,(4,2,2,2,2,2,2,2,2,2,2,2,2,4),(0.,0.607509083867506,
1.21544771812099,1.82923858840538,2.4432020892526,3.06049710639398,3.6778457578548,
4.29148222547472,4.90466427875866,5.43229625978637,5.95979501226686,6.49350136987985,
6.76066500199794,7.02784590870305),.UNSPECIFIED.);
#1220=EDGE_CURVE('E305',#740,#76,#1219,.T.);
#1221=ORIENTED_EDGE('',*,*,#1220,.T.);
#1222=ORIENTED_EDGE('',*,*,#262,.F.);
#1223=CARTESIAN_POINT('',(-1.30847713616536E-13,19.05,-38.0999999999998));
#1224=CARTESIAN_POINT('',(-0.157857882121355,19.0500257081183,-38.0999683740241));
#1225=CARTESIAN_POINT('',(-0.31569948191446,19.0460361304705,-38.1058849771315));
#1226=CARTESIAN_POINT('',(-0.630045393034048,19.030218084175,-38.1293778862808));
#1227=CARTESIAN_POINT('',(-0.786550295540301,19.018393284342,-38.1469487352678));
#1228=CARTESIAN_POINT('',(-1.09621993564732,18.9871816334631,-38.193386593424));
#1229=CARTESIAN_POINT('',(-1.24939824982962,18.9678364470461,-38.2221913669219));
#1230=CARTESIAN_POINT('',(-1.55220090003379,18.9219258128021,-38.2906765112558));
#1231=CARTESIAN_POINT('',(-1.70182497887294,18.8953598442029,-38.3303576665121));
#1232=CARTESIAN_POINT('',(-1.99627206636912,18.8354890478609,-38.4199889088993));
#1233=CARTESIAN_POINT('',(-2.1411032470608,18.8021964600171,-38.4699203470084));
#1234=CARTESIAN_POINT('',(-2.42544309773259,18.7293394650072,-38.5794824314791));
#1235=CARTESIAN_POINT('',(-2.56494968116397,18.6897726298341,-38.6391168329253));
#1236=CARTESIAN_POINT('',(-2.97459036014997,18.5623831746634,-38.83170408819));
#1237=CARTESIAN_POINT('',(-3.23577660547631,18.4658859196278,-38.9783196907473));
#1238=CARTESIAN_POINT('',(-3.74683115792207,18.2469879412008,-39.3134931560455));
#1239=CARTESIAN_POINT('',(-3.99465676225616,18.123254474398,-39.5042553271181));
#1240=CARTESIAN_POINT('',(-4.45518806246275,17.8594814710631,-39.9147045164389));
#1241=CARTESIAN_POINT('',(-4.66788598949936,17.7194383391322,-40.1343979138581));
#1242=CARTESIAN_POINT('',(-4.98279414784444,17.4828284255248,-40.5092485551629));
#1243=CARTESIAN_POINT('',(-5.09634726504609,17.389875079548,-40.6573486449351));
#1244=CARTESIAN_POINT('',(-5.30873539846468,17.2005302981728,-40.9608757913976));
#1245=CARTESIAN_POINT('',(-5.40761259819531,17.1041497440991,-41.1162800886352));
#1246=CARTESIAN_POINT('',(-5.49926131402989,17.006333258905,-41.2749999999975));
#1247=B_SPLINE_CURVE_WITH_KNOTS('',3,(#1223,#1224,#1225,#1226,#1227,#1228,#1229,#1230,#1231,
#1232,#1233,#1234,#1235,#1236,#1237,#1238,#1239,#1240,#1241,#1242,#1243,#1244,#1245,#1246),
.UNSPECIFIED.,.F.,.F.,(4,2,2,2,2,2,2,2,2,2,2,4),(0.,0.473386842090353,0.946552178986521,
1.41713259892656,1.88774696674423,2.3575125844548,2.82746043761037,3.76757387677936,
4.77291677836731,5.77848172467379,6.40333841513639,7.02636274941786),.UNSPECIFIED.);
#1248=EDGE_CURVE('E332',#254,#829,#1247,.T.);
#1249=ORIENTED_EDGE('',*,*,#1248,.T.);
#1250=EDGE_LOOP('',(#1116,#1153,#1154,#1189,#1190,#1221,#1222,#1249));
#1251=FACE_BOUND('',#1250,.T.);
#1252=ADVANCED_FACE('F279',(#1251),#1115,.T.);
#1253=CARTESIAN_POINT('',(0.,4.38530316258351,0.));
#1254=DIRECTION('',(0.,-1.,0.));
#1255=DIRECTION('',(0.,0.,-1.));
#1256=AXIS2_PLACEMENT_3D('',#1253,#1254,#1255);
#1257=CONICAL_SURFACE('',#1256,63.5,1.0471975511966);
#1258=ORIENTED_EDGE('',*,*,#958,.F.);
#1259=CARTESIAN_POINT('',(-41.9234832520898,7.24658914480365,40.8636030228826));
#1260=CARTESIAN_POINT('',(-42.0184345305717,7.14105785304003,41.028051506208));
#1261=CARTESIAN_POINT('',(-42.106288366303,7.03650755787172,41.1972678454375));
#1262=CARTESIAN_POINT('',(-42.2669623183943,6.82998421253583,41.544319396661));
#1263=CARTESIAN_POINT('',(-42.3397751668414,6.72801242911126,41.7221587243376));
#1264=CARTESIAN_POINT('',(-42.469821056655,6.52676707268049,42.0864602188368));
#1265=CARTESIAN_POINT('',(-42.5269587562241,6.42751317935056,42.2729674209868));
#1266=CARTESIAN_POINT('',(-42.6241703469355,6.23306747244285,42.652423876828));
#1267=CARTESIAN_POINT('',(-42.6642460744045,6.13787522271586,42.8453724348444));
#1268=CARTESIAN_POINT('',(-42.7265700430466,5.95196241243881,43.2371158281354));
#1269=CARTESIAN_POINT('',(-42.7487546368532,5.86125888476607,43.4359289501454));
#1270=CARTESIAN_POINT('',(-42.7742051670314,5.68553264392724,43.8371340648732));
#1271=CARTESIAN_POINT('',(-42.7774815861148,5.60050680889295,44.0395240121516));
#1272=CARTESIAN_POINT('',(-42.7644002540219,5.43707603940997,44.4458888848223));
#1273=CARTESIAN_POINT('',(-42.7480813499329,5.35865833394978,44.6498598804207));
#1274=CARTESIAN_POINT('',(-42.695258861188,5.20912001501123,45.0578633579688));
#1275=CARTESIAN_POINT('',(-42.6587584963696,5.13799823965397,45.2618958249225));
#1276=CARTESIAN_POINT('',(-42.5699712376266,5.01078954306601,45.6470899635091));
#1277=CARTESIAN_POINT('',(-42.5196863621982,4.95390876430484,45.8284519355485));
#1278=CARTESIAN_POINT('',(-42.4024276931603,4.8473384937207,46.1878515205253));
#1279=CARTESIAN_POINT('',(-42.3354569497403,4.7976476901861,46.3658897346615));
#1280=CARTESIAN_POINT('',(-42.1849820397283,4.70607277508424,46.7167663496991));
#1281=CARTESIAN_POINT('',(-42.1014898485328,4.66418305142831,46.8896084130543));
#1282=CARTESIAN_POINT('',(-41.9183037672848,4.58871078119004,47.2283711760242));
#1283=CARTESIAN_POINT('',(-41.818613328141,4.55512646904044,47.3942933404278));
#1284=CARTESIAN_POINT('',(-41.6260851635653,4.50280662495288,47.6836992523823));
#1285=CARTESIAN_POINT('',(-41.5361435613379,4.48243532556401,47.8088252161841));
#1286=CARTESIAN_POINT('',(-41.3469830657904,4.44736801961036,48.0526689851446));
#1287=CARTESIAN_POINT('',(-41.2477662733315,4.4326707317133,48.1713882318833));
#1288=CARTESIAN_POINT('',(-41.0403711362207,4.40906232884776,48.4018278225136));
#1289=CARTESIAN_POINT('',(-40.9321730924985,4.40016433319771,48.5135317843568));
#1290=CARTESIAN_POINT('',(-40.7076662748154,4.38827851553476,48.7289001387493));
#1291=CARTESIAN_POINT('',(-40.5913542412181,4.38529308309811,48.8325612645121));
#1292=CARTESIAN_POINT('',(-40.4713577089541,4.38530316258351,48.9317811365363));
#1293=B_SPLINE_CURVE_WITH_KNOTS('',3,(#1259,#1260,#1261,#1262,#1263,#1264,#1265,#1266,#1267,
#1268,#1269,#1270,#1271,#1272,#1273,#1274,#1275,#1276,#1277,#1278,#1279,#1280,#1281,#1282,#1283,
#1284,#1285,#1286,#1287,#1288,#1289,#1290,#1291,#1292),.UNSPECIFIED.,.F.,.F.,(4,2,2,2,2,2,2,2,2,
2,2,2,2,2,2,2,4),(0.,0.651614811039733,1.30354375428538,1.95935421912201,2.61509408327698,
3.2731565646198,3.93085418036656,4.58725008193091,5.2435412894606,5.83255087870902,
6.421452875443,7.00992956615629,7.59828105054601,8.06411139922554,8.52983649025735,
8.99661153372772,9.46357518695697),.UNSPECIFIED.);
#1294=EDGE_CURVE('E558',#932,#902,#1293,.T.);
#1295=ORIENTED_EDGE('',*,*,#1294,.T.);
#1296=ORIENTED_EDGE('',*,*,#903,.F.);
#1297=CARTESIAN_POINT('',(-22.1404866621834,4.38530316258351,59.5151144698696));
#1298=CARTESIAN_POINT('',(-21.9869195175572,4.38529061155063,59.5722732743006));
#1299=CARTESIAN_POINT('',(-21.8311310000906,4.38859823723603,59.6234334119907));
#1300=CARTESIAN_POINT('',(-21.5163670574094,4.4017612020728,59.7135071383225));
#1301=CARTESIAN_POINT('',(-21.3573924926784,4.41161479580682,59.7524239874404));
#1302=CARTESIAN_POINT('',(-21.0379952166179,4.437730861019,59.8176769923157));
#1303=CARTESIAN_POINT('',(-20.8775796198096,4.45397053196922,59.8440571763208));
#1304=CARTESIAN_POINT('',(-20.5559420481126,4.49268791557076,59.8844011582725));
#1305=CARTESIAN_POINT('',(-20.3947200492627,4.51516581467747,59.8983645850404));
#1306=CARTESIAN_POINT('',(-20.0727676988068,4.56611560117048,59.9139607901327));
#1307=CARTESIAN_POINT('',(-19.9120370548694,4.5945826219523,59.9156035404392));
#1308=CARTESIAN_POINT('',(-19.5919782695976,4.65726272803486,59.9068101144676));
#1309=CARTESIAN_POINT('',(-19.4326506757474,4.69147796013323,59.8963694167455));
#1310=CARTESIAN_POINT('',(-19.1164642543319,4.76534552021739,59.86373839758));
#1311=CARTESIAN_POINT('',(-18.9596057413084,4.80499853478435,59.841546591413));
#1312=CARTESIAN_POINT('',(-18.649260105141,4.88942001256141,59.7858361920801));
#1313=CARTESIAN_POINT('',(-18.4957742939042,4.93419042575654,59.7523132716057));
#1314=CARTESIAN_POINT('',(-18.1867799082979,5.03044920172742,59.6728235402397));
#1315=CARTESIAN_POINT('',(-18.0314520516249,5.08213934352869,59.6263977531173));
#1316=CARTESIAN_POINT('',(-17.7262458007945,5.19027993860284,59.5224353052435));
#1317=CARTESIAN_POINT('',(-17.5763694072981,5.24673211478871,59.4648946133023));
#1318=CARTESIAN_POINT('',(-17.1360741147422,5.42262710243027,59.2765813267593));
#1319=CARTESIAN_POINT('',(-16.854829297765,5.54865846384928,59.130075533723));
#1320=CARTESIAN_POINT('',(-16.2936607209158,5.82910706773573,58.7833419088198));
#1321=CARTESIAN_POINT('',(-16.0170735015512,5.98511807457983,58.5790522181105));
#1322=CARTESIAN_POINT('',(-15.504541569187,6.31057933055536,58.1335641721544));
#1323=CARTESIAN_POINT('',(-15.2685976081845,6.48002982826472,57.8923651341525));
#1324=CARTESIAN_POINT('',(-14.9363239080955,6.75052038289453,57.4949322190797));
#1325=CARTESIAN_POINT('',(-14.8247381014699,6.84827313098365,57.3489268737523));
#1326=CARTESIAN_POINT('',(-14.6155341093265,7.04590784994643,57.0492958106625));
#1327=CARTESIAN_POINT('',(-14.5178811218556,7.14578377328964,56.8956904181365));
#1328=CARTESIAN_POINT('',(-14.4271766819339,7.24658914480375,56.7386030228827));
#1329=B_SPLINE_CURVE_WITH_KNOTS('',3,(#1297,#1298,#1299,#1300,#1301,#1302,#1303,#1304,#1305,
#1306,#1307,#1308,#1309,#1310,#1311,#1312,#1313,#1314,#1315,#1316,#1317,#1318,#1319,#1320,#1321,
#1322,#1323,#1324,#1325,#1326,#1327,#1328),.UNSPECIFIED.,.F.,.F.,(4,2,2,2,2,2,2,2,2,2,2,2,2,2,2,
4),(0.,0.491407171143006,0.982683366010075,1.47222123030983,1.96177372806,2.45092995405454,
2.94026927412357,3.42967043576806,3.91925870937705,4.42917957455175,4.93928572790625,
5.95898553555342,7.08738157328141,8.21579848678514,8.83969026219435,9.46199529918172),.UNSPECIFIED.);
#1330=EDGE_CURVE('E553',#900,#870,#1329,.T.);
#1331=ORIENTED_EDGE('',*,*,#1330,.T.);
#1332=ORIENTED_EDGE('',*,*,#871,.F.);
#1333=CARTESIAN_POINT('',(-5.49926131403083,17.0063332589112,41.2749999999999));
#1334=CARTESIAN_POINT('',(-5.40992417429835,17.1016949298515,41.1202618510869));
#1335=CARTESIAN_POINT('',(-5.31367302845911,17.1957173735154,40.9686362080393));
#1336=CARTESIAN_POINT('',(-5.10747578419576,17.3803354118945,40.6725996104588));
#1337=CARTESIAN_POINT('',(-4.99752005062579,17.4709285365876,40.5281938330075));
#1338=CARTESIAN_POINT('',(-4.76305046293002,17.648653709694,40.2464590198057));
#1339=CARTESIAN_POINT('',(-4.63840665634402,17.7357440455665,40.1092114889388));
#1340=CARTESIAN_POINT('',(-4.37570314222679,17.904597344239,39.844514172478));
#1341=CARTESIAN_POINT('',(-4.23763967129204,17.9863588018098,39.7170671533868));
#1342=CARTESIAN_POINT('',(-3.94778677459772,18.1439089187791,39.4726910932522));
#1343=CARTESIAN_POINT('',(-3.79592693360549,18.2196627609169,39.3558228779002));
#1344=CARTESIAN_POINT('',(-3.47976306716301,18.3635515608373,39.1348382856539));
#1345=CARTESIAN_POINT('',(-3.31545796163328,18.4316858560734,39.0307230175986));
#1346=CARTESIAN_POINT('',(-2.97636792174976,18.558719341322,38.8373719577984));
#1347=CARTESIAN_POINT('',(-2.80165194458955,18.6176715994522,38.748050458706));
#1348=CARTESIAN_POINT('',(-2.44221763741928,18.7255697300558,38.585107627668));
#1349=CARTESIAN_POINT('',(-2.25750681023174,18.7745229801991,38.5114747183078));
#1350=CARTESIAN_POINT('',(-1.90602080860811,18.8552466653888,38.3903665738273));
#1351=CARTESIAN_POINT('',(-1.74033874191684,18.8884615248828,38.3406751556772));
#1352=CARTESIAN_POINT('',(-1.40404805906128,18.9459986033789,38.254739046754));
#1353=CARTESIAN_POINT('',(-1.23344069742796,18.9703230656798,38.2184909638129));
#1354=CARTESIAN_POINT('',(-0.886695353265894,19.0097970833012,38.1597269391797));
#1355=CARTESIAN_POINT('',(-0.71051591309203,19.0248352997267,38.1373776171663));
#1356=CARTESIAN_POINT('',(-0.44486970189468,19.0399135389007,38.1149772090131));
#1357=CARTESIAN_POINT('',(-0.356039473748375,19.0436931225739,38.1093643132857));
#1358=CARTESIAN_POINT('',(-0.178144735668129,19.0487369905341,38.101875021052));
#1359=CARTESIAN_POINT('',(-0.0890802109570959,19.0500011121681,38.0999988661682));
#1360=CARTESIAN_POINT('',(3.28778558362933E-13,19.0499999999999,38.1));
#1361=B_SPLINE_CURVE_WITH_KNOTS('',3,(#1333,#1334,#1335,#1336,#1337,#1338,#1339,#1340,#1341,
#1342,#1343,#1344,#1345,#1346,#1347,#1348,#1349,#1350,#1351,#1352,#1353,#1354,#1355,#1356,#1357,
#1358,#1359,#1360),.UNSPECIFIED.,.F.,.F.,(4,2,2,2,2,2,2,2,2,2,2,2,2,4),(0.,0.607509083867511,
1.215447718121,1.82923858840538,2.4432020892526,3.060497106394,3.67784575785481,
4.29148222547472,4.90466427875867,5.43229625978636,5.95979501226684,6.4935013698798,
6.76066500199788,7.02784590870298),.UNSPECIFIED.);
#1362=EDGE_CURVE('E365',#868,#49,#1361,.T.);
#1363=ORIENTED_EDGE('',*,*,#1362,.T.);
#1364=ORIENTED_EDGE('',*,*,#241,.F.);
#1365=CARTESIAN_POINT('',(-32.9955678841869,19.05,19.0500000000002));
#1366=CARTESIAN_POINT('',(-32.9166115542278,19.0500257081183,19.1866931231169));
#1367=CARTESIAN_POINT('',(-32.8428146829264,19.0460361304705,19.3263462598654));
#1368=CARTESIAN_POINT('',(-32.7059871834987,19.030218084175,19.6103242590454));
#1369=CARTESIAN_POINT('',(-32.6429515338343,19.018393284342,19.7546469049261));
#1370=CARTESIAN_POINT('',(-32.5283330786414,18.9871816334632,20.0460476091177));
#1371=CARTESIAN_POINT('',(-32.4766895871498,18.9678364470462,20.1931063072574));
#1372=CARTESIAN_POINT('',(-32.3845981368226,18.9219258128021,20.4895836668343));
#1373=CARTESIAN_POINT('',(-32.3441509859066,18.8953598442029,20.6390024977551));
#1374=CARTESIAN_POINT('',(-32.2745503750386,18.8354890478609,20.9388167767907));
#1375=CARTESIAN_POINT('',(-32.2453766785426,18.8021964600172,21.0892099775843));
#1376=CARTESIAN_POINT('',(-32.1980903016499,18.7293394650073,21.3902365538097));
#1377=CARTESIAN_POINT('',(-32.1799819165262,18.6897726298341,21.5408699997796));
#1378=CARTESIAN_POINT('',(-32.1419470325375,18.5623831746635,21.9919228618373));
#1379=CARTESIAN_POINT('',(-32.1383267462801,18.4658859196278,22.2914245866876));
#1380=CARTESIAN_POINT('',(-32.1730682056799,18.2469879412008,22.9015975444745));
#1381=CARTESIAN_POINT('',(-32.2143602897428,18.123254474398,23.2116018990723));
#1382=CARTESIAN_POINT('',(-32.3395540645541,17.8594814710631,23.8156582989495));
#1383=CARTESIAN_POINT('',(-32.4234651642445,17.7194383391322,24.1097068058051));
#1384=CARTESIAN_POINT('',(-32.5906412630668,17.4828284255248,24.5698505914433));
#1385=CARTESIAN_POINT('',(-32.6621231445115,17.3898750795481,24.742240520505));
#1386=CARTESIAN_POINT('',(-32.8187912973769,17.2005302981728,25.0779376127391));
#1387=CARTESIAN_POINT('',(-32.9039367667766,17.1041497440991,25.2412699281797));
#1388=CARTESIAN_POINT('',(-32.9955678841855,17.006333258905,25.3999999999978));
#1389=B_SPLINE_CURVE_WITH_KNOTS('',3,(#1365,#1366,#1367,#1368,#1369,#1370,#1371,#1372,#1373,
#1374,#1375,#1376,#1377,#1378,#1379,#1380,#1381,#1382,#1383,#1384,#1385,#1386,#1387,#1388),
.UNSPECIFIED.,.F.,.F.,(4,2,2,2,2,2,2,2,2,2,2,4),(0.,0.473386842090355,0.946552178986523,
1.41713259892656,1.88774696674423,2.35751258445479,2.82746043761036,3.76757387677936,
4.77291677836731,5.77848172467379,6.40333841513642,7.02636274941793),.UNSPECIFIED.);
#1390=EDGE_CURVE('E516',#72,#957,#1389,.T.);
#1391=ORIENTED_EDGE('',*,*,#1390,.T.);
#1392=EDGE_LOOP('',(#1258,#1295,#1296,#1331,#1332,#1363,#1364,#1391));
#1393=FACE_BOUND('',#1392,.T.);
#1394=ADVANCED_FACE('F282',(#1393),#1257,.T.);
#1395=CARTESIAN_POINT('',(56.3506599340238,75.6659708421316,9.525));
#1396=DIRECTION('',(0.,-1.,0.));
#1397=DIRECTION('',(0.,0.,-1.));
#1398=AXIS2_PLACEMENT_3D('',#1395,#1396,#1397);
#1399=CYLINDRICAL_SURFACE('',#1398,6.35);
#1400=ORIENTED_EDGE('',*,*,#1010,.F.);
#1401=ORIENTED_EDGE('',*,*,#677,.F.);
#1402=ORIENTED_EDGE('',*,*,#302,.F.);
#1403=ORIENTED_EDGE('',*,*,#653,.F.);
#1404=EDGE_LOOP('',(#1400,#1401,#1402,#1403));
#1405=FACE_BOUND('',#1404,.T.);
#1406=ADVANCED_FACE('F255',(#1405),#1399,.T.);
#1407=CARTESIAN_POINT('',(56.3506599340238,75.6659708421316,-9.525));
#1408=DIRECTION('',(0.,-1.,0.));
#1409=DIRECTION('',(0.,0.,-1.));
#1410=AXIS2_PLACEMENT_3D('',#1407,#1408,#1409);
#1411=CYLINDRICAL_SURFACE('',#1410,6.35);
#1412=ORIENTED_EDGE('',*,*,#1046,.F.);
#1413=ORIENTED_EDGE('',*,*,#660,.F.);
#1414=ORIENTED_EDGE('',*,*,#467,.F.);
#1415=ORIENTED_EDGE('',*,*,#621,.F.);
#1416=EDGE_LOOP('',(#1412,#1413,#1414,#1415));
#1417=FACE_BOUND('',#1416,.T.);
#1418=ADVANCED_FACE('F228',(#1417),#1411,.T.);
#1419=CARTESIAN_POINT('',(-19.9264379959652,75.6659708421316,-53.5636030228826));
#1420=DIRECTION('',(0.,-1.,0.));
#1421=DIRECTION('',(0.,0.,-1.));
#1422=AXIS2_PLACEMENT_3D('',#1419,#1420,#1421);
#1423=CYLINDRICAL_SURFACE('',#1422,6.35);
#1424=ORIENTED_EDGE('',*,*,#1152,.F.);
#1425=ORIENTED_EDGE('',*,*,#805,.F.);
#1426=ORIENTED_EDGE('',*,*,#422,.F.);
#1427=ORIENTED_EDGE('',*,*,#781,.F.);
#1428=EDGE_LOOP('',(#1424,#1425,#1426,#1427));
#1429=FACE_BOUND('',#1428,.T.);
#1430=ADVANCED_FACE('F254',(#1429),#1423,.T.);
#1431=CARTESIAN_POINT('',(-36.4242219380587,75.6659708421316,-44.0386030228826));
#1432=DIRECTION('',(0.,-1.,0.));
#1433=DIRECTION('',(0.,0.,-1.));
#1434=AXIS2_PLACEMENT_3D('',#1431,#1432,#1433);
#1435=CYLINDRICAL_SURFACE('',#1434,6.35);
#1436=ORIENTED_EDGE('',*,*,#1188,.F.);
#1437=ORIENTED_EDGE('',*,*,#788,.F.);
#1438=ORIENTED_EDGE('',*,*,#404,.F.);
#1439=ORIENTED_EDGE('',*,*,#749,.F.);
#1440=EDGE_LOOP('',(#1436,#1437,#1438,#1439));
#1441=FACE_BOUND('',#1440,.T.);
#1442=ADVANCED_FACE('F261',(#1441),#1435,.T.);
#1443=CARTESIAN_POINT('',(-36.4242219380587,75.6659708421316,44.0386030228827));
#1444=DIRECTION('',(0.,-1.,0.));
#1445=DIRECTION('',(0.,0.,-1.));
#1446=AXIS2_PLACEMENT_3D('',#1443,#1444,#1445);
#1447=CYLINDRICAL_SURFACE('',#1446,6.35);
#1448=ORIENTED_EDGE('',*,*,#1294,.F.);
#1449=ORIENTED_EDGE('',*,*,#933,.F.);
#1450=ORIENTED_EDGE('',*,*,#362,.F.);
#1451=ORIENTED_EDGE('',*,*,#909,.F.);
#1452=EDGE_LOOP('',(#1448,#1449,#1450,#1451));
#1453=FACE_BOUND('',#1452,.T.);
#1454=ADVANCED_FACE('F566',(#1453),#1447,.T.);
#1455=CARTESIAN_POINT('',(-19.9264379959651,75.6659708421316,53.5636030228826));
#1456=DIRECTION('',(0.,-1.,0.));
#1457=DIRECTION('',(0.,0.,-1.));
#1458=AXIS2_PLACEMENT_3D('',#1455,#1456,#1457);
#1459=CYLINDRICAL_SURFACE('',#1458,6.35);
#1460=ORIENTED_EDGE('',*,*,#1330,.F.);
#1461=ORIENTED_EDGE('',*,*,#916,.F.);
#1462=ORIENTED_EDGE('',*,*,#344,.F.);
#1463=ORIENTED_EDGE('',*,*,#877,.F.);
#1464=EDGE_LOOP('',(#1460,#1461,#1462,#1463));
#1465=FACE_BOUND('',#1464,.T.);
#1466=ADVANCED_FACE('F563',(#1465),#1459,.T.);
#1467=CARTESIAN_POINT('',(-38.4948291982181,19.05,22.2250000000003));
#1468=DIRECTION('',(0.,-1.,0.));
#1469=DIRECTION('',(0.,0.,-1.));
#1470=AXIS2_PLACEMENT_3D('',#1467,#1468,#1469);
#1471=CYLINDRICAL_SURFACE('',#1470,6.35);
#1472=ORIENTED_EDGE('',*,*,#1390,.F.);
#1473=ORIENTED_EDGE('',*,*,#73,.F.);
#1474=ORIENTED_EDGE('',*,*,#377,.F.);
#1475=ORIENTED_EDGE('',*,*,#964,.F.);
#1476=EDGE_LOOP('',(#1472,#1473,#1474,#1475));
#1477=FACE_BOUND('',#1476,.T.);
#1478=ADVANCED_FACE('F321',(#1477),#1471,.F.);
#1479=CARTESIAN_POINT('',(-38.4948291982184,19.05,-22.2249999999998));
#1480=DIRECTION('',(0.,-1.,0.));
#1481=DIRECTION('',(0.,0.,-1.));
#1482=AXIS2_PLACEMENT_3D('',#1479,#1480,#1481);
#1483=CYLINDRICAL_SURFACE('',#1482,6.35);
#1484=ORIENTED_EDGE('',*,*,#1220,.F.);
#1485=ORIENTED_EDGE('',*,*,#756,.F.);
#1486=ORIENTED_EDGE('',*,*,#387,.F.);
#1487=ORIENTED_EDGE('',*,*,#83,.F.);
#1488=EDGE_LOOP('',(#1484,#1485,#1486,#1487));
#1489=FACE_BOUND('',#1488,.T.);
#1490=ADVANCED_FACE('F315',(#1489),#1483,.F.);
#1491=CARTESIAN_POINT('',(-1.52655665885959E-13,19.05,-44.45));
#1492=DIRECTION('',(0.,-1.,0.));
#1493=DIRECTION('',(0.,0.,-1.));
#1494=AXIS2_PLACEMENT_3D('',#1491,#1492,#1493);
#1495=CYLINDRICAL_SURFACE('',#1494,6.35);
#1496=ORIENTED_EDGE('',*,*,#1248,.F.);
#1497=ORIENTED_EDGE('',*,*,#477,.F.);
#1498=ORIENTED_EDGE('',*,*,#439,.F.);
#1499=ORIENTED_EDGE('',*,*,#836,.F.);
#1500=EDGE_LOOP('',(#1496,#1497,#1498,#1499));
#1501=FACE_BOUND('',#1500,.T.);
#1502=ADVANCED_FACE('F320',(#1501),#1495,.F.);
#1503=CARTESIAN_POINT('',(38.4948291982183,19.05,-22.225));
#1504=DIRECTION('',(0.,-1.,0.));
#1505=DIRECTION('',(0.,0.,-1.));
#1506=AXIS2_PLACEMENT_3D('',#1503,#1504,#1505);
#1507=CYLINDRICAL_SURFACE('',#1506,6.35);
#1508=ORIENTED_EDGE('',*,*,#1078,.F.);
#1509=ORIENTED_EDGE('',*,*,#628,.F.);
#1510=ORIENTED_EDGE('',*,*,#452,.F.);
#1511=ORIENTED_EDGE('',*,*,#484,.F.);
#1512=EDGE_LOOP('',(#1508,#1509,#1510,#1511));
#1513=FACE_BOUND('',#1512,.T.);
#1514=ADVANCED_FACE('F328',(#1513),#1507,.F.);
#1515=CARTESIAN_POINT('',(38.4948291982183,19.05,22.225));
#1516=DIRECTION('',(0.,-1.,0.));
#1517=DIRECTION('',(0.,0.,-1.));
#1518=AXIS2_PLACEMENT_3D('',#1515,#1516,#1517);
#1519=CYLINDRICAL_SURFACE('',#1518,6.35);
#1520=ORIENTED_EDGE('',*,*,#1106,.F.);
#1521=ORIENTED_EDGE('',*,*,#41,.F.);
#1522=ORIENTED_EDGE('',*,*,#317,.F.);
#1523=ORIENTED_EDGE('',*,*,#708,.F.);
#1524=EDGE_LOOP('',(#1520,#1521,#1522,#1523));
#1525=FACE_BOUND('',#1524,.T.);
#1526=ADVANCED_FACE('F353',(#1525),#1519,.F.);
#1527=CARTESIAN_POINT('',(3.19189119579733E-13,19.05,44.45));
#1528=DIRECTION('',(0.,-1.,0.));
#1529=DIRECTION('',(0.,0.,-1.));
#1530=AXIS2_PLACEMENT_3D('',#1527,#1528,#1529);
#1531=CYLINDRICAL_SURFACE('',#1530,6.35);
#1532=ORIENTED_EDGE('',*,*,#1362,.F.);
#1533=ORIENTED_EDGE('',*,*,#884,.F.);
#1534=ORIENTED_EDGE('',*,*,#327,.F.);
#1535=ORIENTED_EDGE('',*,*,#56,.F.);
#1536=EDGE_LOOP('',(#1532,#1533,#1534,#1535));
#1537=FACE_BOUND('',#1536,.T.);
#1538=ADVANCED_FACE('F357',(#1537),#1531,.F.);
#1539=CARTESIAN_POINT('',(0.,0.,0.));
#1540=DIRECTION('',(0.,-1.,0.));
#1541=DIRECTION('',(0.,0.,-1.));
#1542=AXIS2_PLACEMENT_3D('',#1539,#1540,#1541);
#1543=CONICAL_SURFACE('',#1542,7.16279999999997,0.785398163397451);
#1544=CARTESIAN_POINT('',(0.,0.812799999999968,-6.35));
#1545=CARTESIAN_POINT('',(0.,0.804333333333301,-6.35846666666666));
#1546=CARTESIAN_POINT('',(0.,0.795866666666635,-6.36693333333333));
#1547=CARTESIAN_POINT('',(0.,0.778933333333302,-6.38386666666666));
#1548=CARTESIAN_POINT('',(0.,0.770466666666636,-6.39233333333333));
#1549=CARTESIAN_POINT('',(0.,0.753533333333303,-6.40926666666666));
#1550=CARTESIAN_POINT('',(0.,0.745066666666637,-6.41773333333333));
#1551=CARTESIAN_POINT('',(0.,0.728133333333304,-6.43466666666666));
#1552=CARTESIAN_POINT('',(0.,0.719666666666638,-6.44313333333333));
#1553=CARTESIAN_POINT('',(0.,0.702733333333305,-6.46006666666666));
#1554=CARTESIAN_POINT('',(0.,0.694266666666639,-6.46853333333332));
#1555=CARTESIAN_POINT('',(0.,0.677333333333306,-6.48546666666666));
#1556=CARTESIAN_POINT('',(0.,0.66886666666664,-6.49393333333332));
#1557=CARTESIAN_POINT('',(0.,0.651933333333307,-6.51086666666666));
#1558=CARTESIAN_POINT('',(0.,0.643466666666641,-6.51933333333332));
#1559=CARTESIAN_POINT('',(0.,0.626533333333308,-6.53626666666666));
#1560=CARTESIAN_POINT('',(0.,0.618066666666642,-6.54473333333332));
#1561=CARTESIAN_POINT('',(0.,0.601133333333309,-6.56166666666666));
#1562=CARTESIAN_POINT('',(0.,0.592666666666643,-6.57013333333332));
#1563=CARTESIAN_POINT('',(0.,0.57573333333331,-6.58706666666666));
#1564=CARTESIAN_POINT('',(0.,0.567266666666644,-6.59553333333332));
#1565=CARTESIAN_POINT('',(0.,0.550333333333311,-6.61246666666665));
#1566=CARTESIAN_POINT('',(0.,0.541866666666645,-6.62093333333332));
#1567=CARTESIAN_POINT('',(0.,0.524933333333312,-6.63786666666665));
#1568=CARTESIAN_POINT('',(0.,0.516466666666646,-6.64633333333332));
#1569=CARTESIAN_POINT('',(0.,0.499533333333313,-6.66326666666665));
#1570=CARTESIAN_POINT('',(0.,0.491066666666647,-6.67173333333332));
#1571=CARTESIAN_POINT('',(0.,0.474133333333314,-6.68866666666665));
#1572=CARTESIAN_POINT('',(0.,0.465666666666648,-6.69713333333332));
#1573=CARTESIAN_POINT('',(0.,0.448733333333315,-6.71406666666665));
#1574=CARTESIAN_POINT('',(0.,0.440266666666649,-6.72253333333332));
#1575=CARTESIAN_POINT('',(0.,0.423333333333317,-6.73946666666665));
#1576=CARTESIAN_POINT('',(0.,0.41486666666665,-6.74793333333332));
#1577=CARTESIAN_POINT('',(0.,0.397933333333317,-6.76486666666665));
#1578=CARTESIAN_POINT('',(0.,0.389466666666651,-6.77333333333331));
#1579=CARTESIAN_POINT('',(0.,0.372533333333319,-6.79026666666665));
#1580=CARTESIAN_POINT('',(0.,0.364066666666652,-6.79873333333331));
#1581=CARTESIAN_POINT('',(0.,0.34713333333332,-6.81566666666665));
#1582=CARTESIAN_POINT('',(0.,0.338666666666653,-6.82413333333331));
#1583=CARTESIAN_POINT('',(0.,0.32173333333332,-6.84106666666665));
#1584=CARTESIAN_POINT('',(0.,0.313266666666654,-6.84953333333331));
#1585=CARTESIAN_POINT('',(0.,0.296333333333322,-6.86646666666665));
#1586=CARTESIAN_POINT('',(0.,0.287866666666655,-6.87493333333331));
#1587=CARTESIAN_POINT('',(0.,0.270933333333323,-6.89186666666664));
#1588=CARTESIAN_POINT('',(0.,0.262466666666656,-6.90033333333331));
#1589=CARTESIAN_POINT('',(0.,0.245533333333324,-6.91726666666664));
#1590=CARTESIAN_POINT('',(0.,0.237066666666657,-6.92573333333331));
#1591=CARTESIAN_POINT('',(0.,0.220133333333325,-6.94266666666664));
#1592=CARTESIAN_POINT('',(0.,0.211666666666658,-6.95113333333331));
#1593=CARTESIAN_POINT('',(0.,0.194733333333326,-6.96806666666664));
#1594=CARTESIAN_POINT('',(0.,0.186266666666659,-6.97653333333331));
#1595=CARTESIAN_POINT('',(0.,0.169333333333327,-6.99346666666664));
#1596=CARTESIAN_POINT('',(0.,0.16086666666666,-7.00193333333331));
#1597=CARTESIAN_POINT('',(0.,0.143933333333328,-7.01886666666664));
#1598=CARTESIAN_POINT('',(0.,0.135466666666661,-7.02733333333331));
#1599=CARTESIAN_POINT('',(0.,0.118533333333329,-7.04426666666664));
#1600=CARTESIAN_POINT('',(0.,0.110066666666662,-7.0527333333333));
#1601=CARTESIAN_POINT('',(0.,0.0931333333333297,-7.06966666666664));
#1602=CARTESIAN_POINT('',(0.,0.0846666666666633,-7.0781333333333));
#1603=CARTESIAN_POINT('',(0.,0.0677333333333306,-7.09506666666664));
#1604=CARTESIAN_POINT('',(0.,0.0592666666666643,-7.1035333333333));
#1605=CARTESIAN_POINT('',(0.,0.0423333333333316,-7.12046666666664));
#1606=CARTESIAN_POINT('',(0.,0.0338666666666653,-7.1289333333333));
#1607=CARTESIAN_POINT('',(0.,0.0169333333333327,-7.14586666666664));
#1608=CARTESIAN_POINT('',(0.,0.00846666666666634,-7.1543333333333));
#1609=CARTESIAN_POINT('',(0.,0.,-7.16279999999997));
#1610=B_SPLINE_CURVE_WITH_KNOTS('',3,(#1544,#1545,#1546,#1547,#1548,#1549,#1550,#1551,#1552,
#1553,#1554,#1555,#1556,#1557,#1558,#1559,#1560,#1561,#1562,#1563,#1564,#1565,#1566,#1567,#1568,
#1569,#1570,#1571,#1572,#1573,#1574,#1575,#1576,#1577,#1578,#1579,#1580,#1581,#1582,#1583,#1584,
#1585,#1586,#1587,#1588,#1589,#1590,#1591,#1592,#1593,#1594,#1595,#1596,#1597,#1598,#1599,#1600,
#1601,#1602,#1603,#1604,#1605,#1606,#1607,#1608,#1609),.UNSPECIFIED.,.F.,.F.,(4,2,2,2,2,2,2,2,2,
2,2,2,2,2,2,2,2,2,2,2,2,2,2,2,2,2,2,2,2,2,2,2,4),(0.,0.0359210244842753,0.0718420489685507,
0.107763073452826,0.143684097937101,0.179605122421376,0.215526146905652,0.251447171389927,
0.287368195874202,0.323289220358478,0.359210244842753,0.395131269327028,0.431052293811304,
0.466973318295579,0.502894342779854,0.538815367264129,0.574736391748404,0.61065741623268,
0.646578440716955,0.68249946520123,0.718420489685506,0.754341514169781,0.790262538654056,
0.826183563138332,0.862104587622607,0.898025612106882,0.933946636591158,0.969867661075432,
1.00578868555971,1.04170971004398,1.07763073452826,1.11355175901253,1.14947278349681),.UNSPECIFIED.);
#1611=EDGE_CURVE('BSEAM362',#500,#279,#1610,.T.);
#1612=ORIENTED_EDGE('',*,*,#501,.F.);
#1613=ORIENTED_EDGE('',*,*,#280,.F.);
#1614=ORIENTED_EDGE('',*,*,#1611,.T.);
#1615=ORIENTED_EDGE('',*,*,#1611,.F.);
#1616=EDGE_LOOP('',(#1612,#1614,#1613,#1615));
#1617=FACE_BOUND('',#1616,.T.);
#1618=ADVANCED_FACE('F362',(#1617),#1543,.F.);
#1619=CARTESIAN_POINT('',(0.,18.2371999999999,0.));
#1620=DIRECTION('',(0.,1.,0.));
#1621=DIRECTION('',(0.,0.,1.));
#1622=AXIS2_PLACEMENT_3D('',#1619,#1620,#1621);
#1623=CONICAL_SURFACE('',#1622,6.35,0.785398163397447);
#1624=ORIENTED_EDGE('',*,*,#232,.F.);
#1625=EDGE_LOOP('',(#1624));
#1626=FACE_BOUND('',#1625,.T.);
#1627=ORIENTED_EDGE('',*,*,#509,.F.);
#1628=EDGE_LOOP('',(#1627));
#1629=FACE_BOUND('',#1628,.T.);
#1630=ADVANCED_FACE('F725',(#1626,#1629),#1623,.F.);
#1631=CARTESIAN_POINT('',(-14.63675,15.875,25.3515946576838));
#1632=DIRECTION('',(0.,1.,0.));
#1633=DIRECTION('',(0.,0.,1.));
#1634=AXIS2_PLACEMENT_3D('',#1631,#1632,#1633);
#1635=CYLINDRICAL_SURFACE('',#1634,2.54);
#1636=CARTESIAN_POINT('',(-14.63675,18.6436,25.3515946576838));
#1637=DIRECTION('',(0.,1.,0.));
#1638=DIRECTION('',(0.,0.,1.));
#1639=AXIS2_PLACEMENT_3D('',#1636,#1637,#1638);
#1640=CIRCLE('',#1639,2.54);
#1641=CARTESIAN_POINT('',(-14.63675,18.6436,27.8915946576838));
#1642=VERTEX_POINT('',#1641);
#1643=EDGE_CURVE('E382',#1642,#1642,#1640,.T.);
#1644=ORIENTED_EDGE('',*,*,#1643,.T.);
#1645=EDGE_LOOP('',(#1644));
#1646=FACE_BOUND('',#1645,.T.);
#1647=CARTESIAN_POINT('',(-14.63675,15.875,25.3515946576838));
#1648=DIRECTION('',(0.,1.,0.));
#1649=DIRECTION('',(0.,0.,1.));
#1650=AXIS2_PLACEMENT_3D('',#1647,#1648,#1649);
#1651=CIRCLE('',#1650,2.54);
#1652=CARTESIAN_POINT('',(-14.63675,15.875,27.8915946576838));
#1653=VERTEX_POINT('',#1652);
#1654=EDGE_CURVE('E609',#1653,#1653,#1651,.T.);
#1655=ORIENTED_EDGE('',*,*,#1654,.F.);
#1656=EDGE_LOOP('',(#1655));
#1657=FACE_BOUND('',#1656,.T.);
#1658=ADVANCED_FACE('F678',(#1646,#1657),#1635,.F.);
#1659=CARTESIAN_POINT('',(-14.63675,15.875,25.3515946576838));
#1660=DIRECTION('',(0.,1.,0.));
#1661=DIRECTION('',(0.,0.,1.));
#1662=AXIS2_PLACEMENT_3D('',#1659,#1660,#1661);
#1663=PLANE('',#1662);
#1664=ORIENTED_EDGE('',*,*,#1654,.T.);
#1665=EDGE_LOOP('',(#1664));
#1666=FACE_BOUND('',#1665,.T.);
#1667=ADVANCED_FACE('F741',(#1666),#1663,.T.);
#1668=CARTESIAN_POINT('',(-25.3515946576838,15.875,14.63675));
#1669=DIRECTION('',(0.,1.,0.));
#1670=DIRECTION('',(0.,0.,1.));
#1671=AXIS2_PLACEMENT_3D('',#1668,#1669,#1670);
#1672=CYLINDRICAL_SURFACE('',#1671,2.54);
#1673=CARTESIAN_POINT('',(-25.3515946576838,18.6436,14.63675));
#1674=DIRECTION('',(0.,1.,0.));
#1675=DIRECTION('',(0.,0.,1.));
#1676=AXIS2_PLACEMENT_3D('',#1673,#1674,#1675);
#1677=CIRCLE('',#1676,2.54);
#1678=CARTESIAN_POINT('',(-25.3515946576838,18.6436,17.17675));
#1679=VERTEX_POINT('',#1678);
#1680=EDGE_CURVE('E11',#1679,#1679,#1677,.T.);
#1681=ORIENTED_EDGE('',*,*,#1680,.T.);
#1682=EDGE_LOOP('',(#1681));
#1683=FACE_BOUND('',#1682,.T.);
#1684=CARTESIAN_POINT('',(-25.3515946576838,15.875,14.63675));
#1685=DIRECTION('',(0.,1.,0.));
#1686=DIRECTION('',(0.,0.,1.));
#1687=AXIS2_PLACEMENT_3D('',#1684,#1685,#1686);
#1688=CIRCLE('',#1687,2.54);
#1689=CARTESIAN_POINT('',(-25.3515946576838,15.875,17.17675));
#1690=VERTEX_POINT('',#1689);
#1691=EDGE_CURVE('E1107',#1690,#1690,#1688,.T.);
#1692=ORIENTED_EDGE('',*,*,#1691,.F.);
#1693=EDGE_LOOP('',(#1692));
#1694=FACE_BOUND('',#1693,.T.);
#1695=ADVANCED_FACE('F746',(#1683,#1694),#1672,.F.);
#1696=CARTESIAN_POINT('',(-25.3515946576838,15.875,14.63675));
#1697=DIRECTION('',(0.,1.,0.));
#1698=DIRECTION('',(0.,0.,1.));
#1699=AXIS2_PLACEMENT_3D('',#1696,#1697,#1698);
#1700=PLANE('',#1699);
#1701=ORIENTED_EDGE('',*,*,#1691,.T.);
#1702=EDGE_LOOP('',(#1701));
#1703=FACE_BOUND('',#1702,.T.);
#1704=ADVANCED_FACE('F753',(#1703),#1700,.T.);
#1705=CARTESIAN_POINT('',(-29.2735,15.875,0.));
#1706=DIRECTION('',(0.,1.,0.));
#1707=DIRECTION('',(0.,0.,1.));
#1708=AXIS2_PLACEMENT_3D('',#1705,#1706,#1707);
#1709=CYLINDRICAL_SURFACE('',#1708,2.54);
#1710=CARTESIAN_POINT('',(-29.2735,18.6436,0.));
#1711=DIRECTION('',(0.,1.,0.));
#1712=DIRECTION('',(0.,0.,1.));
#1713=AXIS2_PLACEMENT_3D('',#1710,#1711,#1712);
#1714=CIRCLE('',#1713,2.54);
#1715=CARTESIAN_POINT('',(-29.2735,18.6436,2.5399999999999));
#1716=VERTEX_POINT('',#1715);
#1717=EDGE_CURVE('E40',#1716,#1716,#1714,.T.);
#1718=ORIENTED_EDGE('',*,*,#1717,.T.);
#1719=EDGE_LOOP('',(#1718));
#1720=FACE_BOUND('',#1719,.T.);
#1721=CARTESIAN_POINT('',(-29.2735,15.875,0.));
#1722=DIRECTION('',(0.,1.,0.));
#1723=DIRECTION('',(0.,0.,1.));
#1724=AXIS2_PLACEMENT_3D('',#1721,#1722,#1723);
#1725=CIRCLE('',#1724,2.54);
#1726=CARTESIAN_POINT('',(-29.2735,15.875,2.5399999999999));
#1727=VERTEX_POINT('',#1726);
#1728=EDGE_CURVE('E1099',#1727,#1727,#1725,.T.);
#1729=ORIENTED_EDGE('',*,*,#1728,.F.);
#1730=EDGE_LOOP('',(#1729));
#1731=FACE_BOUND('',#1730,.T.);
#1732=ADVANCED_FACE('F450',(#1720,#1731),#1709,.F.);
#1733=CARTESIAN_POINT('',(-29.2735,15.875,0.));
#1734=DIRECTION('',(0.,1.,0.));
#1735=DIRECTION('',(0.,0.,1.));
#1736=AXIS2_PLACEMENT_3D('',#1733,#1734,#1735);
#1737=PLANE('',#1736);
#1738=ORIENTED_EDGE('',*,*,#1728,.T.);
#1739=EDGE_LOOP('',(#1738));
#1740=FACE_BOUND('',#1739,.T.);
#1741=ADVANCED_FACE('F765',(#1740),#1737,.T.);
#1742=CARTESIAN_POINT('',(-25.3515946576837,15.875,-14.6367500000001));
#1743=DIRECTION('',(0.,1.,0.));
#1744=DIRECTION('',(0.,0.,1.));
#1745=AXIS2_PLACEMENT_3D('',#1742,#1743,#1744);
#1746=CYLINDRICAL_SURFACE('',#1745,2.54);
#1747=CARTESIAN_POINT('',(-25.3515946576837,18.6436,-14.6367500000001));
#1748=DIRECTION('',(0.,1.,0.));
#1749=DIRECTION('',(0.,0.,1.));
#1750=AXIS2_PLACEMENT_3D('',#1747,#1748,#1749);
#1751=CIRCLE('',#1750,2.54);
#1752=CARTESIAN_POINT('',(-25.3515946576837,18.6436,-12.0967500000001));
#1753=VERTEX_POINT('',#1752);
#1754=EDGE_CURVE('E445',#1753,#1753,#1751,.T.);
#1755=ORIENTED_EDGE('',*,*,#1754,.T.);
#1756=EDGE_LOOP('',(#1755));
#1757=FACE_BOUND('',#1756,.T.);
#1758=CARTESIAN_POINT('',(-25.3515946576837,15.875,-14.6367500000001));
#1759=DIRECTION('',(0.,1.,0.));
#1760=DIRECTION('',(0.,0.,1.));
#1761=AXIS2_PLACEMENT_3D('',#1758,#1759,#1760);
#1762=CIRCLE('',#1761,2.54);
#1763=CARTESIAN_POINT('',(-25.3515946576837,15.875,-12.0967500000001));
#1764=VERTEX_POINT('',#1763);
#1765=EDGE_CURVE('E1095',#1764,#1764,#1762,.T.);
#1766=ORIENTED_EDGE('',*,*,#1765,.F.);
#1767=EDGE_LOOP('',(#1766));
#1768=FACE_BOUND('',#1767,.T.);
#1769=ADVANCED_FACE('F770',(#1757,#1768),#1746,.F.);
#1770=CARTESIAN_POINT('',(-25.3515946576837,15.875,-14.6367500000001));
#1771=DIRECTION('',(0.,1.,0.));
#1772=DIRECTION('',(0.,0.,1.));
#1773=AXIS2_PLACEMENT_3D('',#1770,#1771,#1772);
#1774=PLANE('',#1773);
#1775=ORIENTED_EDGE('',*,*,#1765,.T.);
#1776=EDGE_LOOP('',(#1775));
#1777=FACE_BOUND('',#1776,.T.);
#1778=ADVANCED_FACE('F778',(#1777),#1774,.T.);
#1779=CARTESIAN_POINT('',(-14.6367499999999,15.875,-25.3515946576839));
#1780=DIRECTION('',(0.,1.,0.));
#1781=DIRECTION('',(0.,0.,1.));
#1782=AXIS2_PLACEMENT_3D('',#1779,#1780,#1781);
#1783=CYLINDRICAL_SURFACE('',#1782,2.54);
#1784=CARTESIAN_POINT('',(-14.6367499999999,18.6436,-25.3515946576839));
#1785=DIRECTION('',(0.,1.,0.));
#1786=DIRECTION('',(0.,0.,1.));
#1787=AXIS2_PLACEMENT_3D('',#1784,#1785,#1786);
#1788=CIRCLE('',#1787,2.54);
#1789=CARTESIAN_POINT('',(-14.6367499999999,18.6436,-22.8115946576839));
#1790=VERTEX_POINT('',#1789);
#1791=EDGE_CURVE('E442',#1790,#1790,#1788,.T.);
#1792=ORIENTED_EDGE('',*,*,#1791,.T.);
#1793=EDGE_LOOP('',(#1792));
#1794=FACE_BOUND('',#1793,.T.);
#1795=CARTESIAN_POINT('',(-14.6367499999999,15.875,-25.3515946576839));
#1796=DIRECTION('',(0.,1.,0.));
#1797=DIRECTION('',(0.,0.,1.));
#1798=AXIS2_PLACEMENT_3D('',#1795,#1796,#1797);
#1799=CIRCLE('',#1798,2.54);
#1800=CARTESIAN_POINT('',(-14.6367499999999,15.875,-22.8115946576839));
#1801=VERTEX_POINT('',#1800);
#1802=EDGE_CURVE('E1094',#1801,#1801,#1799,.T.);
#1803=ORIENTED_EDGE('',*,*,#1802,.F.);
#1804=EDGE_LOOP('',(#1803));
#1805=FACE_BOUND('',#1804,.T.);
#1806=ADVANCED_FACE('F783',(#1794,#1805),#1783,.F.);
#1807=CARTESIAN_POINT('',(-14.6367499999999,15.875,-25.3515946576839));
#1808=DIRECTION('',(0.,1.,0.));
#1809=DIRECTION('',(0.,0.,1.));
#1810=AXIS2_PLACEMENT_3D('',#1807,#1808,#1809);
#1811=PLANE('',#1810);
#1812=ORIENTED_EDGE('',*,*,#1802,.T.);
#1813=EDGE_LOOP('',(#1812));
#1814=FACE_BOUND('',#1813,.T.);
#1815=ADVANCED_FACE('F791',(#1814),#1811,.T.);
#1816=CARTESIAN_POINT('',(1.96023752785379E-13,15.875,-29.2735));
#1817=DIRECTION('',(0.,1.,0.));
#1818=DIRECTION('',(0.,0.,1.));
#1819=AXIS2_PLACEMENT_3D('',#1816,#1817,#1818);
#1820=CYLINDRICAL_SURFACE('',#1819,2.54);
#1821=CARTESIAN_POINT('',(1.96023752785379E-13,18.6436,-29.2735));
#1822=DIRECTION('',(0.,1.,0.));
#1823=DIRECTION('',(0.,0.,1.));
#1824=AXIS2_PLACEMENT_3D('',#1821,#1822,#1823);
#1825=CIRCLE('',#1824,2.54);
#1826=CARTESIAN_POINT('',(1.96023752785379E-13,18.6436,-26.7335));
#1827=VERTEX_POINT('',#1826);
#1828=EDGE_CURVE('E439',#1827,#1827,#1825,.T.);
#1829=ORIENTED_EDGE('',*,*,#1828,.T.);
#1830=EDGE_LOOP('',(#1829));
#1831=FACE_BOUND('',#1830,.T.);
#1832=CARTESIAN_POINT('',(1.96023752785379E-13,15.875,-29.2735));
#1833=DIRECTION('',(0.,1.,0.));
#1834=DIRECTION('',(0.,0.,1.));
#1835=AXIS2_PLACEMENT_3D('',#1832,#1833,#1834);
#1836=CIRCLE('',#1835,2.54);
#1837=CARTESIAN_POINT('',(1.96023752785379E-13,15.875,-26.7335));
#1838=VERTEX_POINT('',#1837);
#1839=EDGE_CURVE('E1096',#1838,#1838,#1836,.T.);
#1840=ORIENTED_EDGE('',*,*,#1839,.F.);
#1841=EDGE_LOOP('',(#1840));
#1842=FACE_BOUND('',#1841,.T.);
#1843=ADVANCED_FACE('F796',(#1831,#1842),#1820,.F.);
#1844=CARTESIAN_POINT('',(1.96023752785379E-13,15.875,-29.2735));
#1845=DIRECTION('',(0.,1.,0.));
#1846=DIRECTION('',(0.,0.,1.));
#1847=AXIS2_PLACEMENT_3D('',#1844,#1845,#1846);
#1848=PLANE('',#1847);
#1849=ORIENTED_EDGE('',*,*,#1839,.T.);
#1850=EDGE_LOOP('',(#1849));
#1851=FACE_BOUND('',#1850,.T.);
#1852=ADVANCED_FACE('F804',(#1851),#1848,.T.);
#1853=CARTESIAN_POINT('',(14.6367500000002,15.875,-25.3515946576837));
#1854=DIRECTION('',(0.,1.,0.));
#1855=DIRECTION('',(0.,0.,1.));
#1856=AXIS2_PLACEMENT_3D('',#1853,#1854,#1855);
#1857=CYLINDRICAL_SURFACE('',#1856,2.54);
#1858=CARTESIAN_POINT('',(14.6367500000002,18.6436,-25.3515946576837));
#1859=DIRECTION('',(0.,1.,0.));
#1860=DIRECTION('',(0.,0.,1.));
#1861=AXIS2_PLACEMENT_3D('',#1858,#1859,#1860);
#1862=CIRCLE('',#1861,2.54);
#1863=CARTESIAN_POINT('',(14.6367500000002,18.6436,-22.8115946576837));
#1864=VERTEX_POINT('',#1863);
#1865=EDGE_CURVE('E436',#1864,#1864,#1862,.T.);
#1866=ORIENTED_EDGE('',*,*,#1865,.T.);
#1867=EDGE_LOOP('',(#1866));
#1868=FACE_BOUND('',#1867,.T.);
#1869=CARTESIAN_POINT('',(14.6367500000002,15.875,-25.3515946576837));
#1870=DIRECTION('',(0.,1.,0.));
#1871=DIRECTION('',(0.,0.,1.));
#1872=AXIS2_PLACEMENT_3D('',#1869,#1870,#1871);
#1873=CIRCLE('',#1872,2.54);
#1874=CARTESIAN_POINT('',(14.6367500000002,15.875,-22.8115946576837));
#1875=VERTEX_POINT('',#1874);
#1876=EDGE_CURVE('E1102',#1875,#1875,#1873,.T.);
#1877=ORIENTED_EDGE('',*,*,#1876,.F.);
#1878=EDGE_LOOP('',(#1877));
#1879=FACE_BOUND('',#1878,.T.);
#1880=ADVANCED_FACE('F809',(#1868,#1879),#1857,.F.);
#1881=CARTESIAN_POINT('',(14.6367500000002,15.875,-25.3515946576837));
#1882=DIRECTION('',(0.,1.,0.));
#1883=DIRECTION('',(0.,0.,1.));
#1884=AXIS2_PLACEMENT_3D('',#1881,#1882,#1883);
#1885=PLANE('',#1884);
#1886=ORIENTED_EDGE('',*,*,#1876,.T.);
#1887=EDGE_LOOP('',(#1886));
#1888=FACE_BOUND('',#1887,.T.);
#1889=ADVANCED_FACE('F817',(#1888),#1885,.T.);
#1890=CARTESIAN_POINT('',(25.3515946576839,15.875,-14.6367499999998));
#1891=DIRECTION('',(0.,1.,0.));
#1892=DIRECTION('',(0.,0.,1.));
#1893=AXIS2_PLACEMENT_3D('',#1890,#1891,#1892);
#1894=CYLINDRICAL_SURFACE('',#1893,2.54);
#1895=CARTESIAN_POINT('',(25.3515946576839,18.6436,-14.6367499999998));
#1896=DIRECTION('',(0.,1.,0.));
#1897=DIRECTION('',(0.,0.,1.));
#1898=AXIS2_PLACEMENT_3D('',#1895,#1896,#1897);
#1899=CIRCLE('',#1898,2.54);
#1900=CARTESIAN_POINT('',(25.3515946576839,18.6436,-12.0967499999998));
#1901=VERTEX_POINT('',#1900);
#1902=EDGE_CURVE('E433',#1901,#1901,#1899,.T.);
#1903=ORIENTED_EDGE('',*,*,#1902,.T.);
#1904=EDGE_LOOP('',(#1903));
#1905=FACE_BOUND('',#1904,.T.);
#1906=CARTESIAN_POINT('',(25.3515946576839,15.875,-14.6367499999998));
#1907=DIRECTION('',(0.,1.,0.));
#1908=DIRECTION('',(0.,0.,1.));
#1909=AXIS2_PLACEMENT_3D('',#1906,#1907,#1908);
#1910=CIRCLE('',#1909,2.54);
#1911=CARTESIAN_POINT('',(25.3515946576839,15.875,-12.0967499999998));
#1912=VERTEX_POINT('',#1911);
#1913=EDGE_CURVE('E1117',#1912,#1912,#1910,.T.);
#1914=ORIENTED_EDGE('',*,*,#1913,.F.);
#1915=EDGE_LOOP('',(#1914));
#1916=FACE_BOUND('',#1915,.T.);
#1917=ADVANCED_FACE('F822',(#1905,#1916),#1894,.F.);
#1918=CARTESIAN_POINT('',(25.3515946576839,15.875,-14.6367499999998));
#1919=DIRECTION('',(0.,1.,0.));
#1920=DIRECTION('',(0.,0.,1.));
#1921=AXIS2_PLACEMENT_3D('',#1918,#1919,#1920);
#1922=PLANE('',#1921);
#1923=ORIENTED_EDGE('',*,*,#1913,.T.);
#1924=EDGE_LOOP('',(#1923));
#1925=FACE_BOUND('',#1924,.T.);
#1926=ADVANCED_FACE('F830',(#1925),#1922,.T.);
#1927=CARTESIAN_POINT('',(29.2735,15.875,3.03576608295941E-13));
#1928=DIRECTION('',(0.,1.,0.));
#1929=DIRECTION('',(0.,0.,1.));
#1930=AXIS2_PLACEMENT_3D('',#1927,#1928,#1929);
#1931=CYLINDRICAL_SURFACE('',#1930,2.54);
#1932=CARTESIAN_POINT('',(29.2735,18.6436,3.03576608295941E-13));
#1933=DIRECTION('',(0.,1.,0.));
#1934=DIRECTION('',(0.,0.,1.));
#1935=AXIS2_PLACEMENT_3D('',#1932,#1933,#1934);
#1936=CIRCLE('',#1935,2.54);
#1937=CARTESIAN_POINT('',(29.2735,18.6436,2.54000000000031));
#1938=VERTEX_POINT('',#1937);
#1939=EDGE_CURVE('E430',#1938,#1938,#1936,.T.);
#1940=ORIENTED_EDGE('',*,*,#1939,.T.);
#1941=EDGE_LOOP('',(#1940));
#1942=FACE_BOUND('',#1941,.T.);
#1943=CARTESIAN_POINT('',(29.2735,15.875,3.03576608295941E-13));
#1944=DIRECTION('',(0.,1.,0.));
#1945=DIRECTION('',(0.,0.,1.));
#1946=AXIS2_PLACEMENT_3D('',#1943,#1944,#1945);
#1947=CIRCLE('',#1946,2.54);
#1948=CARTESIAN_POINT('',(29.2735,15.875,2.54000000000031));
#1949=VERTEX_POINT('',#1948);
#1950=EDGE_CURVE('E1120',#1949,#1949,#1947,.T.);
#1951=ORIENTED_EDGE('',*,*,#1950,.F.);
#1952=EDGE_LOOP('',(#1951));
#1953=FACE_BOUND('',#1952,.T.);
#1954=ADVANCED_FACE('F835',(#1942,#1953),#1931,.F.);
#1955=CARTESIAN_POINT('',(29.2735,15.875,3.03576608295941E-13));
#1956=DIRECTION('',(0.,1.,0.));
#1957=DIRECTION('',(0.,0.,1.));
#1958=AXIS2_PLACEMENT_3D('',#1955,#1956,#1957);
#1959=PLANE('',#1958);
#1960=ORIENTED_EDGE('',*,*,#1950,.T.);
#1961=EDGE_LOOP('',(#1960));
#1962=FACE_BOUND('',#1961,.T.);
#1963=ADVANCED_FACE('F843',(#1962),#1959,.T.);
#1964=CARTESIAN_POINT('',(25.3515946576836,15.875,14.6367500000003));
#1965=DIRECTION('',(0.,1.,0.));
#1966=DIRECTION('',(0.,0.,1.));
#1967=AXIS2_PLACEMENT_3D('',#1964,#1965,#1966);
#1968=CYLINDRICAL_SURFACE('',#1967,2.54);
#1969=CARTESIAN_POINT('',(25.3515946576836,18.6436,14.6367500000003));
#1970=DIRECTION('',(0.,1.,0.));
#1971=DIRECTION('',(0.,0.,1.));
#1972=AXIS2_PLACEMENT_3D('',#1969,#1970,#1971);
#1973=CIRCLE('',#1972,2.54);
#1974=CARTESIAN_POINT('',(25.3515946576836,18.6436,17.1767500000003));
#1975=VERTEX_POINT('',#1974);
#1976=EDGE_CURVE('E427',#1975,#1975,#1973,.T.);
#1977=ORIENTED_EDGE('',*,*,#1976,.T.);
#1978=EDGE_LOOP('',(#1977));
#1979=FACE_BOUND('',#1978,.T.);
#1980=CARTESIAN_POINT('',(25.3515946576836,15.875,14.6367500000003));
#1981=DIRECTION('',(0.,1.,0.));
#1982=DIRECTION('',(0.,0.,1.));
#1983=AXIS2_PLACEMENT_3D('',#1980,#1981,#1982);
#1984=CIRCLE('',#1983,2.54);
#1985=CARTESIAN_POINT('',(25.3515946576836,15.875,17.1767500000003));
#1986=VERTEX_POINT('',#1985);
#1987=EDGE_CURVE('E1123',#1986,#1986,#1984,.T.);
#1988=ORIENTED_EDGE('',*,*,#1987,.F.);
#1989=EDGE_LOOP('',(#1988));
#1990=FACE_BOUND('',#1989,.T.);
#1991=ADVANCED_FACE('F848',(#1979,#1990),#1968,.F.);
#1992=CARTESIAN_POINT('',(25.3515946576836,15.875,14.6367500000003));
#1993=DIRECTION('',(0.,1.,0.));
#1994=DIRECTION('',(0.,0.,1.));
#1995=AXIS2_PLACEMENT_3D('',#1992,#1993,#1994);
#1996=PLANE('',#1995);
#1997=ORIENTED_EDGE('',*,*,#1987,.T.);
#1998=EDGE_LOOP('',(#1997));
#1999=FACE_BOUND('',#1998,.T.);
#2000=ADVANCED_FACE('F856',(#1999),#1996,.T.);
#2001=CARTESIAN_POINT('',(14.6367499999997,15.875,25.351594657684));
#2002=DIRECTION('',(0.,1.,0.));
#2003=DIRECTION('',(0.,0.,1.));
#2004=AXIS2_PLACEMENT_3D('',#2001,#2002,#2003);
#2005=CYLINDRICAL_SURFACE('',#2004,2.54);
#2006=CARTESIAN_POINT('',(14.6367499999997,18.6436,25.351594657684));
#2007=DIRECTION('',(0.,1.,0.));
#2008=DIRECTION('',(0.,0.,1.));
#2009=AXIS2_PLACEMENT_3D('',#2006,#2007,#2008);
#2010=CIRCLE('',#2009,2.54);
#2011=CARTESIAN_POINT('',(14.6367499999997,18.6436,27.891594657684));
#2012=VERTEX_POINT('',#2011);
#2013=EDGE_CURVE('E424',#2012,#2012,#2010,.T.);
#2014=ORIENTED_EDGE('',*,*,#2013,.T.);
#2015=EDGE_LOOP('',(#2014));
#2016=FACE_BOUND('',#2015,.T.);
#2017=CARTESIAN_POINT('',(14.6367499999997,15.875,25.351594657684));
#2018=DIRECTION('',(0.,1.,0.));
#2019=DIRECTION('',(0.,0.,1.));
#2020=AXIS2_PLACEMENT_3D('',#2017,#2018,#2019);
#2021=CIRCLE('',#2020,2.54);
#2022=CARTESIAN_POINT('',(14.6367499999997,15.875,27.891594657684));
#2023=VERTEX_POINT('',#2022);
#2024=EDGE_CURVE('E1126',#2023,#2023,#2021,.T.);
#2025=ORIENTED_EDGE('',*,*,#2024,.F.);
#2026=EDGE_LOOP('',(#2025));
#2027=FACE_BOUND('',#2026,.T.);
#2028=ADVANCED_FACE('F861',(#2016,#2027),#2005,.F.);
#2029=CARTESIAN_POINT('',(14.6367499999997,15.875,25.351594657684));
#2030=DIRECTION('',(0.,1.,0.));
#2031=DIRECTION('',(0.,0.,1.));
#2032=AXIS2_PLACEMENT_3D('',#2029,#2030,#2031);
#2033=PLANE('',#2032);
#2034=ORIENTED_EDGE('',*,*,#2024,.T.);
#2035=EDGE_LOOP('',(#2034));
#2036=FACE_BOUND('',#2035,.T.);
#2037=ADVANCED_FACE('F869',(#2036),#2033,.T.);
#2038=CARTESIAN_POINT('',(-3.98986399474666E-13,15.875,29.2735));
#2039=DIRECTION('',(0.,1.,0.));
#2040=DIRECTION('',(0.,0.,1.));
#2041=AXIS2_PLACEMENT_3D('',#2038,#2039,#2040);
#2042=CYLINDRICAL_SURFACE('',#2041,2.54);
#2043=CARTESIAN_POINT('',(-3.98986399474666E-13,18.6436,29.2735));
#2044=DIRECTION('',(0.,1.,0.));
#2045=DIRECTION('',(0.,0.,1.));
#2046=AXIS2_PLACEMENT_3D('',#2043,#2044,#2045);
#2047=CIRCLE('',#2046,2.54);
#2048=CARTESIAN_POINT('',(-3.98986399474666E-13,18.6436,31.8135));
#2049=VERTEX_POINT('',#2048);
#2050=EDGE_CURVE('E421',#2049,#2049,#2047,.T.);
#2051=ORIENTED_EDGE('',*,*,#2050,.T.);
#2052=EDGE_LOOP('',(#2051));
#2053=FACE_BOUND('',#2052,.T.);
#2054=CARTESIAN_POINT('',(-3.98986399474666E-13,15.875,29.2735));
#2055=DIRECTION('',(0.,1.,0.));
#2056=DIRECTION('',(0.,0.,1.));
#2057=AXIS2_PLACEMENT_3D('',#2054,#2055,#2056);
#2058=CIRCLE('',#2057,2.54);
#2059=CARTESIAN_POINT('',(-3.98986399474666E-13,15.875,31.8135));
#2060=VERTEX_POINT('',#2059);
#2061=EDGE_CURVE('E1129',#2060,#2060,#2058,.T.);
#2062=ORIENTED_EDGE('',*,*,#2061,.F.);
#2063=EDGE_LOOP('',(#2062));
#2064=FACE_BOUND('',#2063,.T.);
#2065=ADVANCED_FACE('F874',(#2053,#2064),#2042,.F.);
#2066=CARTESIAN_POINT('',(-3.98986399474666E-13,15.875,29.2735));
#2067=DIRECTION('',(0.,1.,0.));
#2068=DIRECTION('',(0.,0.,1.));
#2069=AXIS2_PLACEMENT_3D('',#2066,#2067,#2068);
#2070=PLANE('',#2069);
#2071=ORIENTED_EDGE('',*,*,#2061,.T.);
#2072=EDGE_LOOP('',(#2071));
#2073=FACE_BOUND('',#2072,.T.);
#2074=ADVANCED_FACE('F882',(#2073),#2070,.T.);
#2075=CARTESIAN_POINT('',(-14.63675,18.6436,25.3515946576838));
#2076=DIRECTION('',(0.,1.,0.));
#2077=DIRECTION('',(0.,0.,1.));
#2078=AXIS2_PLACEMENT_3D('',#2075,#2076,#2077);
#2079=CONICAL_SURFACE('',#2078,2.54,0.785398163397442);
#2080=ORIENTED_EDGE('',*,*,#100,.F.);
#2081=EDGE_LOOP('',(#2080));
#2082=FACE_BOUND('',#2081,.T.);
#2083=ORIENTED_EDGE('',*,*,#1643,.F.);
#2084=EDGE_LOOP('',(#2083));
#2085=FACE_BOUND('',#2084,.T.);
#2086=ADVANCED_FACE('F887',(#2082,#2085),#2079,.F.);
#2087=CARTESIAN_POINT('',(-3.98986399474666E-13,18.6436,29.2735));
#2088=DIRECTION('',(0.,1.,0.));
#2089=DIRECTION('',(0.,0.,1.));
#2090=AXIS2_PLACEMENT_3D('',#2087,#2088,#2089);
#2091=CONICAL_SURFACE('',#2090,2.54,0.785398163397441);
#2092=ORIENTED_EDGE('',*,*,#111,.F.);
#2093=EDGE_LOOP('',(#2092));
#2094=FACE_BOUND('',#2093,.T.);
#2095=ORIENTED_EDGE('',*,*,#2050,.F.);
#2096=EDGE_LOOP('',(#2095));
#2097=FACE_BOUND('',#2096,.T.);
#2098=ADVANCED_FACE('F989',(#2094,#2097),#2091,.F.);
#2099=CARTESIAN_POINT('',(14.6367499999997,18.6436,25.351594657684));
#2100=DIRECTION('',(0.,1.,0.));
#2101=DIRECTION('',(0.,0.,1.));
#2102=AXIS2_PLACEMENT_3D('',#2099,#2100,#2101);
#2103=CONICAL_SURFACE('',#2102,2.54,0.785398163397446);
#2104=ORIENTED_EDGE('',*,*,#122,.F.);
#2105=EDGE_LOOP('',(#2104));
#2106=FACE_BOUND('',#2105,.T.);
#2107=ORIENTED_EDGE('',*,*,#2013,.F.);
#2108=EDGE_LOOP('',(#2107));
#2109=FACE_BOUND('',#2108,.T.);
#2110=ADVANCED_FACE('F999',(#2106,#2109),#2103,.F.);
#2111=CARTESIAN_POINT('',(25.3515946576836,18.6436,14.6367500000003));
#2112=DIRECTION('',(0.,1.,0.));
#2113=DIRECTION('',(0.,0.,1.));
#2114=AXIS2_PLACEMENT_3D('',#2111,#2112,#2113);
#2115=CONICAL_SURFACE('',#2114,2.54,0.785398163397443);
#2116=ORIENTED_EDGE('',*,*,#133,.F.);
#2117=EDGE_LOOP('',(#2116));
#2118=FACE_BOUND('',#2117,.T.);
#2119=ORIENTED_EDGE('',*,*,#1976,.F.);
#2120=EDGE_LOOP('',(#2119));
#2121=FACE_BOUND('',#2120,.T.);
#2122=ADVANCED_FACE('F1009',(#2118,#2121),#2115,.F.);
#2123=CARTESIAN_POINT('',(29.2735,18.6436,3.03576608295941E-13));
#2124=DIRECTION('',(0.,1.,0.));
#2125=DIRECTION('',(0.,0.,1.));
#2126=AXIS2_PLACEMENT_3D('',#2123,#2124,#2125);
#2127=CONICAL_SURFACE('',#2126,2.54,0.785398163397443);
#2128=ORIENTED_EDGE('',*,*,#144,.F.);
#2129=EDGE_LOOP('',(#2128));
#2130=FACE_BOUND('',#2129,.T.);
#2131=ORIENTED_EDGE('',*,*,#1939,.F.);
#2132=EDGE_LOOP('',(#2131));
#2133=FACE_BOUND('',#2132,.T.);
#2134=ADVANCED_FACE('F1019',(#2130,#2133),#2127,.F.);
#2135=CARTESIAN_POINT('',(25.3515946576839,18.6436,-14.6367499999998));
#2136=DIRECTION('',(0.,1.,0.));
#2137=DIRECTION('',(0.,0.,1.));
#2138=AXIS2_PLACEMENT_3D('',#2135,#2136,#2137);
#2139=CONICAL_SURFACE('',#2138,2.54,0.785398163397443);
#2140=ORIENTED_EDGE('',*,*,#155,.F.);
#2141=EDGE_LOOP('',(#2140));
#2142=FACE_BOUND('',#2141,.T.);
#2143=ORIENTED_EDGE('',*,*,#1902,.F.);
#2144=EDGE_LOOP('',(#2143));
#2145=FACE_BOUND('',#2144,.T.);
#2146=ADVANCED_FACE('F1029',(#2142,#2145),#2139,.F.);
#2147=CARTESIAN_POINT('',(14.6367500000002,18.6436,-25.3515946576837));
#2148=DIRECTION('',(0.,1.,0.));
#2149=DIRECTION('',(0.,0.,1.));
#2150=AXIS2_PLACEMENT_3D('',#2147,#2148,#2149);
#2151=CONICAL_SURFACE('',#2150,2.54,0.785398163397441);
#2152=ORIENTED_EDGE('',*,*,#166,.F.);
#2153=EDGE_LOOP('',(#2152));
#2154=FACE_BOUND('',#2153,.T.);
#2155=ORIENTED_EDGE('',*,*,#1865,.F.);
#2156=EDGE_LOOP('',(#2155));
#2157=FACE_BOUND('',#2156,.T.);
#2158=ADVANCED_FACE('F1039',(#2154,#2157),#2151,.F.);
#2159=CARTESIAN_POINT('',(1.96023752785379E-13,18.6436,-29.2735));
#2160=DIRECTION('',(0.,1.,0.));
#2161=DIRECTION('',(0.,0.,1.));
#2162=AXIS2_PLACEMENT_3D('',#2159,#2160,#2161);
#2163=CONICAL_SURFACE('',#2162,2.54,0.785398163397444);
#2164=ORIENTED_EDGE('',*,*,#177,.F.);
#2165=EDGE_LOOP('',(#2164));
#2166=FACE_BOUND('',#2165,.T.);
#2167=ORIENTED_EDGE('',*,*,#1828,.F.);
#2168=EDGE_LOOP('',(#2167));
#2169=FACE_BOUND('',#2168,.T.);
#2170=ADVANCED_FACE('F1049',(#2166,#2169),#2163,.F.);
#2171=CARTESIAN_POINT('',(-14.6367499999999,18.6436,-25.3515946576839));
#2172=DIRECTION('',(0.,1.,0.));
#2173=DIRECTION('',(0.,0.,1.));
#2174=AXIS2_PLACEMENT_3D('',#2171,#2172,#2173);
#2175=CONICAL_SURFACE('',#2174,2.54,0.785398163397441);
#2176=ORIENTED_EDGE('',*,*,#188,.F.);
#2177=EDGE_LOOP('',(#2176));
#2178=FACE_BOUND('',#2177,.T.);
#2179=ORIENTED_EDGE('',*,*,#1791,.F.);
#2180=EDGE_LOOP('',(#2179));
#2181=FACE_BOUND('',#2180,.T.);
#2182=ADVANCED_FACE('F462',(#2178,#2181),#2175,.F.);
#2183=CARTESIAN_POINT('',(-25.3515946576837,18.6436,-14.6367500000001));
#2184=DIRECTION('',(0.,1.,0.));
#2185=DIRECTION('',(0.,0.,1.));
#2186=AXIS2_PLACEMENT_3D('',#2183,#2184,#2185);
#2187=CONICAL_SURFACE('',#2186,2.54,0.785398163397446);
#2188=ORIENTED_EDGE('',*,*,#199,.F.);
#2189=EDGE_LOOP('',(#2188));
#2190=FACE_BOUND('',#2189,.T.);
#2191=ORIENTED_EDGE('',*,*,#1754,.F.);
#2192=EDGE_LOOP('',(#2191));
#2193=FACE_BOUND('',#2192,.T.);
#2194=ADVANCED_FACE('F455',(#2190,#2193),#2187,.F.);
#2195=CARTESIAN_POINT('',(-29.2735,18.6436,0.));
#2196=DIRECTION('',(0.,1.,0.));
#2197=DIRECTION('',(0.,0.,1.));
#2198=AXIS2_PLACEMENT_3D('',#2195,#2196,#2197);
#2199=CONICAL_SURFACE('',#2198,2.54,0.785398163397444);
#2200=ORIENTED_EDGE('',*,*,#210,.F.);
#2201=EDGE_LOOP('',(#2200));
#2202=FACE_BOUND('',#2201,.T.);
#2203=ORIENTED_EDGE('',*,*,#1717,.F.);
#2204=EDGE_LOOP('',(#2203));
#2205=FACE_BOUND('',#2204,.T.);
#2206=ADVANCED_FACE('F453',(#2202,#2205),#2199,.F.);
#2207=CARTESIAN_POINT('',(-25.3515946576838,18.6436,14.63675));
#2208=DIRECTION('',(0.,1.,0.));
#2209=DIRECTION('',(0.,0.,1.));
#2210=AXIS2_PLACEMENT_3D('',#2207,#2208,#2209);
#2211=CONICAL_SURFACE('',#2210,2.54,0.785398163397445);
#2212=ORIENTED_EDGE('',*,*,#221,.F.);
#2213=EDGE_LOOP('',(#2212));
#2214=FACE_BOUND('',#2213,.T.);
#2215=ORIENTED_EDGE('',*,*,#1680,.F.);
#2216=EDGE_LOOP('',(#2215));
#2217=FACE_BOUND('',#2216,.T.);
#2218=ADVANCED_FACE('F34',(#2214,#2217),#2211,.F.);
#2219=CLOSED_SHELL('',(#60,#87,#267,#471,#488,#584,#632,#664,#712,#760,#792,#840,#888,#920,#968,
#1110,#1252,#1394,#1406,#1418,#1430,#1442,#1454,#1466,#1478,#1490,#1502,#1514,#1526,#1538,#1618,
#1630,#1658,#1667,#1695,#1704,#1732,#1741,#1769,#1778,#1806,#1815,#1843,#1852,#1880,#1889,#1917,
#1926,#1954,#1963,#1991,#2000,#2028,#2037,#2065,#2074,#2086,#2098,#2110,#2122,#2134,#2146,#2158,
#2170,#2182,#2194,#2206,#2218));
#2220=MANIFOLD_SOLID_BREP('B2',#2219);
#2221=ADVANCED_BREP_SHAPE_REPRESENTATION('',(#18,#2220),#14);
#2222=SHAPE_DEFINITION_REPRESENTATION(#9,#2221);
ENDSEC;
END-ISO-10303-21;
